FUNCTION "FC_GRP_80_R22" : VOID
TITLE =GROUP =80-R22
{ S7_language := '9(1) Angielski (Stany Zjednoczone)  11.01.2022  09:45:15' }
VERSION : 0.1


VAR_TEMP
  CL : "UDT_CABINET";	//CABINET LOCAL
  CR : "UDT_CABINET";	//CABINET REMOTE
  RelError : BOOL ;	//ERROR RELEASE
  RelErrorCL : BOOL ;	//ERROR RELEASE FROM CABINET LOCAL
  RelErrorCR : BOOL ;	//ERROR RELEASE FROM CABINET REMOTE
  RelControl : BOOL ;	//CONTROL RELEASE
  RelControlCL : BOOL ;	//CONTROL RELEASE FROM CABINET LOCAL
  RelControlCR : BOOL ;	//CONTROL RELEASE FROM CABINET REMOTE
  ErrorConfirm : BOOL ;	//ERROR CONFIRM
  AutoOn : BOOL ;	//AUTOMATIC ON
  AutoOff : BOOL ;	//AUTOMATIC OFF
  AutoOnTemp : BOOL ;
  AutoOffTemp : BOOL ;
  TrDummy : REAL ;	//place holder
  Runtime_DI : DINT ;
  Runtime_R : REAL ;
END_VAR
BEGIN
NETWORK
TITLE =GLOBAL SIGNALS

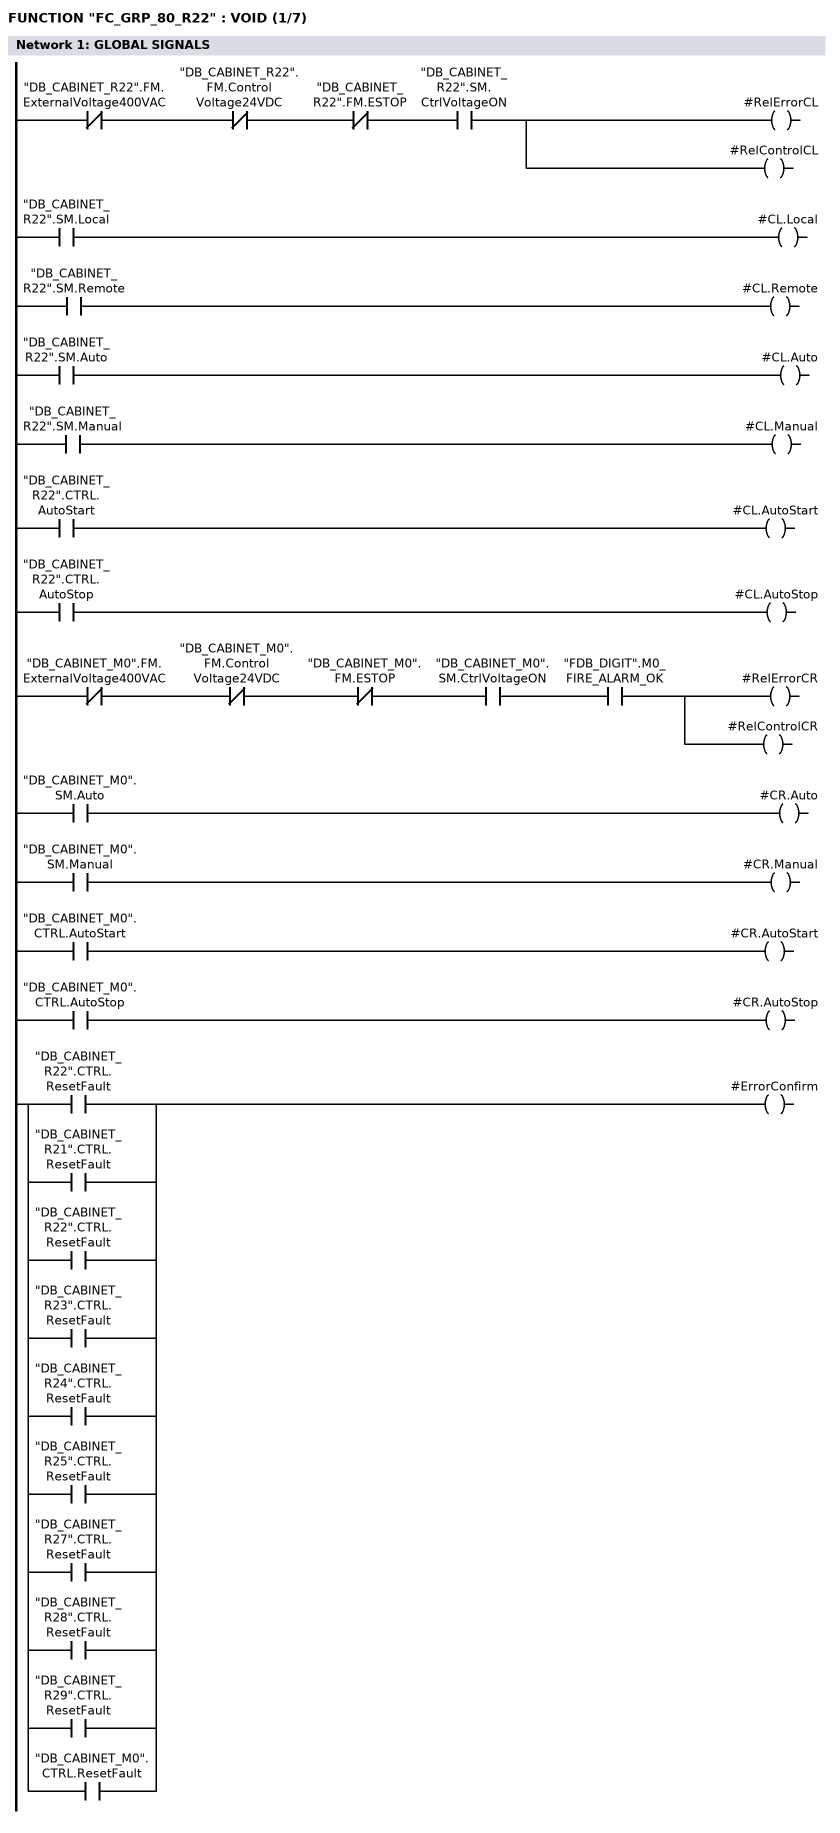
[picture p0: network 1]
// LOCAL
      UN    "DB_CABINET_R22".FM.ExternalVoltage400VAC;
      UN    "DB_CABINET_R22".FM.ControlVoltage24VDC;
      UN    "DB_CABINET_R22".FM.ESTOP;
      U     "DB_CABINET_R22".SM.CtrlVoltageON;
      =     #RelErrorCL;
      =     #RelControlCL;

      U     "DB_CABINET_R22".SM.Local;
      =     #CL.Local;
      U     "DB_CABINET_R22".SM.Remote;
      =     #CL.Remote;
      U     "DB_CABINET_R22".SM.Auto;
      =     #CL.Auto;
      U     "DB_CABINET_R22".SM.Manual;
      =     #CL.Manual;
      U     "DB_CABINET_R22".CTRL.AutoStart;
      =     #CL.AutoStart;
      U     "DB_CABINET_R22".CTRL.AutoStop;
      =     #CL.AutoStop;

// REMOTE
      UN    "DB_CABINET_M0".FM.ExternalVoltage400VAC;
      UN    "DB_CABINET_M0".FM.ControlVoltage24VDC;
      UN    "DB_CABINET_M0".FM.ESTOP;
      U     "DB_CABINET_M0".SM.CtrlVoltageON;
      U     "FDB_DIGIT".M0_FIRE_ALARM_OK;
      =     #RelErrorCR;
      =     #RelControlCR;

      U     "DB_CABINET_M0".SM.Auto;
      =     #CR.Auto;
      U     "DB_CABINET_M0".SM.Manual;
      =     #CR.Manual;
      U     "DB_CABINET_M0".CTRL.AutoStart;
      =     #CR.AutoStart;
      U     "DB_CABINET_M0".CTRL.AutoStop;
      =     #CR.AutoStop;

      U     "DB_CABINET_R22".CTRL.ResetFault;
      O     "DB_CABINET_R21".CTRL.ResetFault;
      O     "DB_CABINET_R22".CTRL.ResetFault;
      O     "DB_CABINET_R23".CTRL.ResetFault;
      O     "DB_CABINET_R24".CTRL.ResetFault;
      O     "DB_CABINET_R25".CTRL.ResetFault;
      O     "DB_CABINET_R27".CTRL.ResetFault;
      O     "DB_CABINET_R28".CTRL.ResetFault;
      O     "DB_CABINET_R29".CTRL.ResetFault;
      O     "DB_CABINET_M0".CTRL.ResetFault;
      =     #ErrorConfirm;
NETWORK
TITLE ==80TAN01-U1 CONTROL/ERROR RELEASE

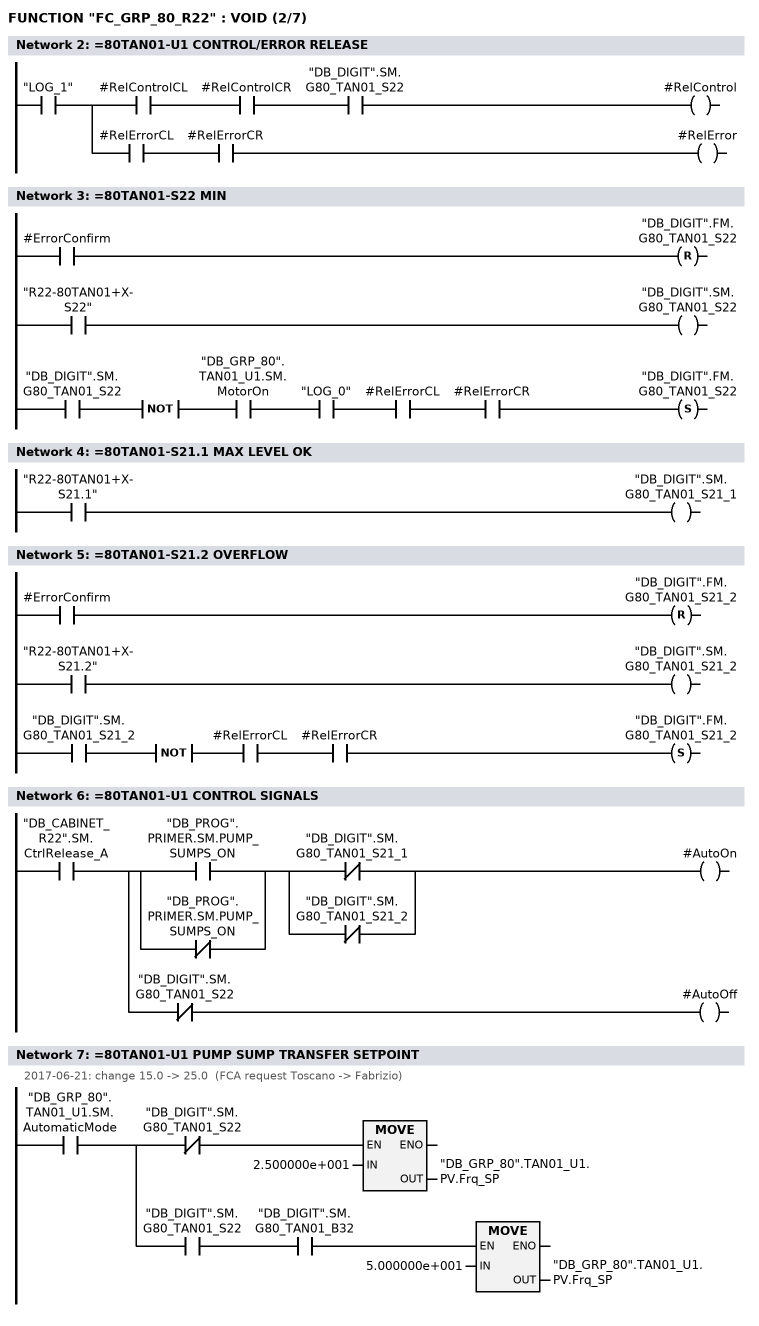
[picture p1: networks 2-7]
      U     "LOG_1";
      =     L     18.0;
      U     L     18.0;
      U     #RelControlCL;
      U     #RelControlCR;
      U     "DB_DIGIT".SM.G80_TAN01_S22;
      =     #RelControl;
      U     L     18.0;
      U     #RelErrorCL;
      U     #RelErrorCR;
      =     #RelError;
NETWORK
TITLE ==80TAN01-S22 MIN

      U     #ErrorConfirm;
      R     "DB_DIGIT".FM.G80_TAN01_S22;
      U     "R22-80TAN01+X-S22";
      =     "DB_DIGIT".SM.G80_TAN01_S22;
      U     "DB_DIGIT".SM.G80_TAN01_S22;
      NOT   ;
      U     "DB_GRP_80".TAN01_U1.SM.MotorOn;
      U     "LOG_0";
      U     #RelErrorCL;
      U     #RelErrorCR;
      S     "DB_DIGIT".FM.G80_TAN01_S22;
      NOP   0;
NETWORK
TITLE ==80TAN01-S21.1 MAX LEVEL OK

      U     "R22-80TAN01+X-S21.1";
      =     "DB_DIGIT".SM.G80_TAN01_S21_1;
NETWORK
TITLE ==80TAN01-S21.2 OVERFLOW

      U     #ErrorConfirm;
      R     "DB_DIGIT".FM.G80_TAN01_S21_2;
      U     "R22-80TAN01+X-S21.2";
      =     "DB_DIGIT".SM.G80_TAN01_S21_2;
      U     "DB_DIGIT".SM.G80_TAN01_S21_2;
      NOT   ;
      U     #RelErrorCL;
      U     #RelErrorCR;
      S     "DB_DIGIT".FM.G80_TAN01_S21_2;
      NOP   0;
NETWORK
TITLE ==80TAN01-U1 CONTROL SIGNALS

      U     "DB_CABINET_R22".SM.CtrlRelease_A;
      =     L     18.0;
      U     L     18.0;
      U(    ;
      O     "DB_PROG".PRIMER.SM.PUMP_SUMPS_ON;
      ON    "DB_PROG".PRIMER.SM.PUMP_SUMPS_ON;
      )     ;
      U(    ;
      ON    "DB_DIGIT".SM.G80_TAN01_S21_1;
      ON    "DB_DIGIT".SM.G80_TAN01_S21_2;
      )     ;
      =     #AutoOn;
      U     L     18.0;
      UN    "DB_DIGIT".SM.G80_TAN01_S22;
      =     #AutoOff;
NETWORK
TITLE ==80TAN01-U1 PUMP SUMP TRANSFER SETPOINT
//2017-06-21: change 15.0 -> 25.0  (FCA request Toscano -> Fabrizio)
      U     "DB_GRP_80".TAN01_U1.SM.AutomaticMode;
      =     L     18.0;
      U     L     18.0;
      UN    "DB_DIGIT".SM.G80_TAN01_S22;
      SPBNB _001;
      L     2.500000e+001;
      T     "DB_GRP_80".TAN01_U1.PV.Frq_SP;
_001: NOP   0;
      U     L     18.0;
      U     "DB_DIGIT".SM.G80_TAN01_S22;
      U     "DB_DIGIT".SM.G80_TAN01_B32;
      SPBNB _002;
      L     5.000000e+001;
      T     "DB_GRP_80".TAN01_U1.PV.Frq_SP;
_002: NOP   0;
NETWORK
TITLE =RESET USING ESTOP ON THE CABINET

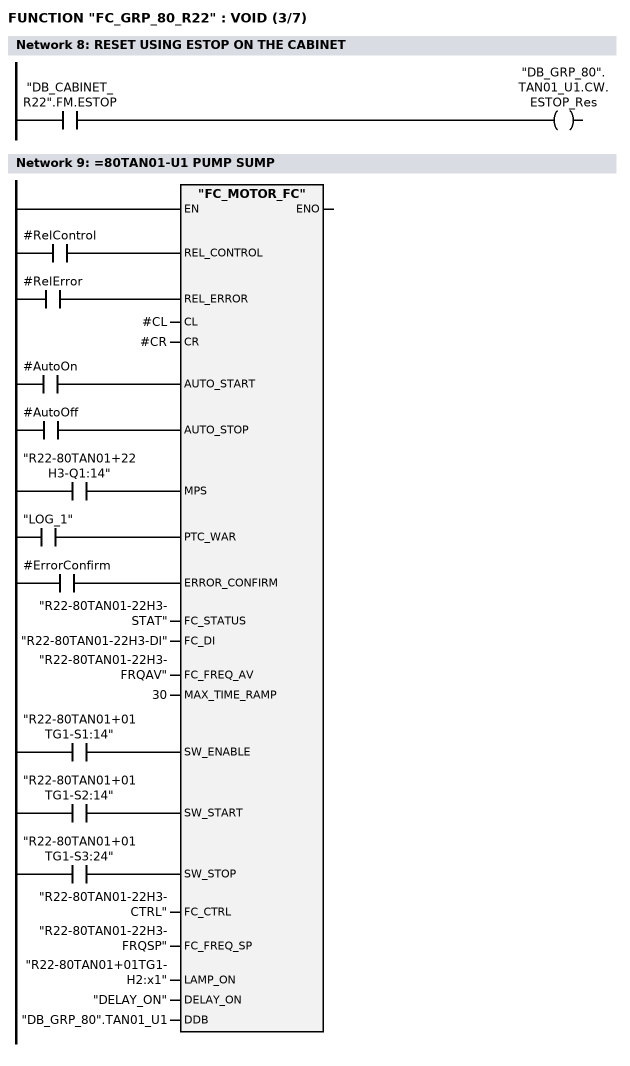
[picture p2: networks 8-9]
      U     "DB_CABINET_R22".FM.ESTOP;
      =     "DB_GRP_80".TAN01_U1.CW.ESTOP_Res;
NETWORK
TITLE ==80TAN01-U1 PUMP SUMP

      U     #RelControl;
      =     L     18.0;
      BLD   103;
      U     #RelError;
      =     L     18.1;
      BLD   103;
      U     #AutoOn;
      =     L     18.2;
      BLD   103;
      U     #AutoOff;
      =     L     18.3;
      BLD   103;
      U     "R22-80TAN01+22H3-Q1:14";
      =     L     18.4;
      BLD   103;
      U     "LOG_1";
      =     L     18.5;
      BLD   103;
      U     #ErrorConfirm;
      =     L     18.6;
      BLD   103;
      U     "R22-80TAN01+01TG1-S1:14";
      =     L     18.7;
      BLD   103;
      U     "R22-80TAN01+01TG1-S2:14";
      =     L     19.0;
      BLD   103;
      U     "R22-80TAN01+01TG1-S3:24";
      =     L     19.1;
      BLD   103;
      CALL "FC_MOTOR_FC" (
           REL_CONTROL              := L     18.0,
           REL_ERROR                := L     18.1,
           CL                       := #CL,
           CR                       := #CR,
           AUTO_START               := L     18.2,
           AUTO_STOP                := L     18.3,
           MPS                      := L     18.4,
           PTC_WAR                  := L     18.5,
           ERROR_CONFIRM            := L     18.6,
           FC_STATUS                := "R22-80TAN01-22H3-STAT",
           FC_DI                    := "R22-80TAN01-22H3-DI",
           FC_FREQ_AV               := "R22-80TAN01-22H3-FRQAV",
           MAX_TIME_RAMP            := 30,
           SW_ENABLE                := L     18.7,
           SW_START                 := L     19.0,
           SW_STOP                  := L     19.1,
           FC_CTRL                  := "R22-80TAN01-22H3-CTRL",
           FC_FREQ_SP               := "R22-80TAN01-22H3-FRQSP",
           LAMP_ON                  := "R22-80TAN01+01TG1-H2:x1",
           DELAY_ON                 := "DELAY_ON",
           DDB                      := "DB_GRP_80".TAN01_U1);
      NOP   0;
NETWORK
TITLE ==80TAN01-S32F PRESSURE MONITORING

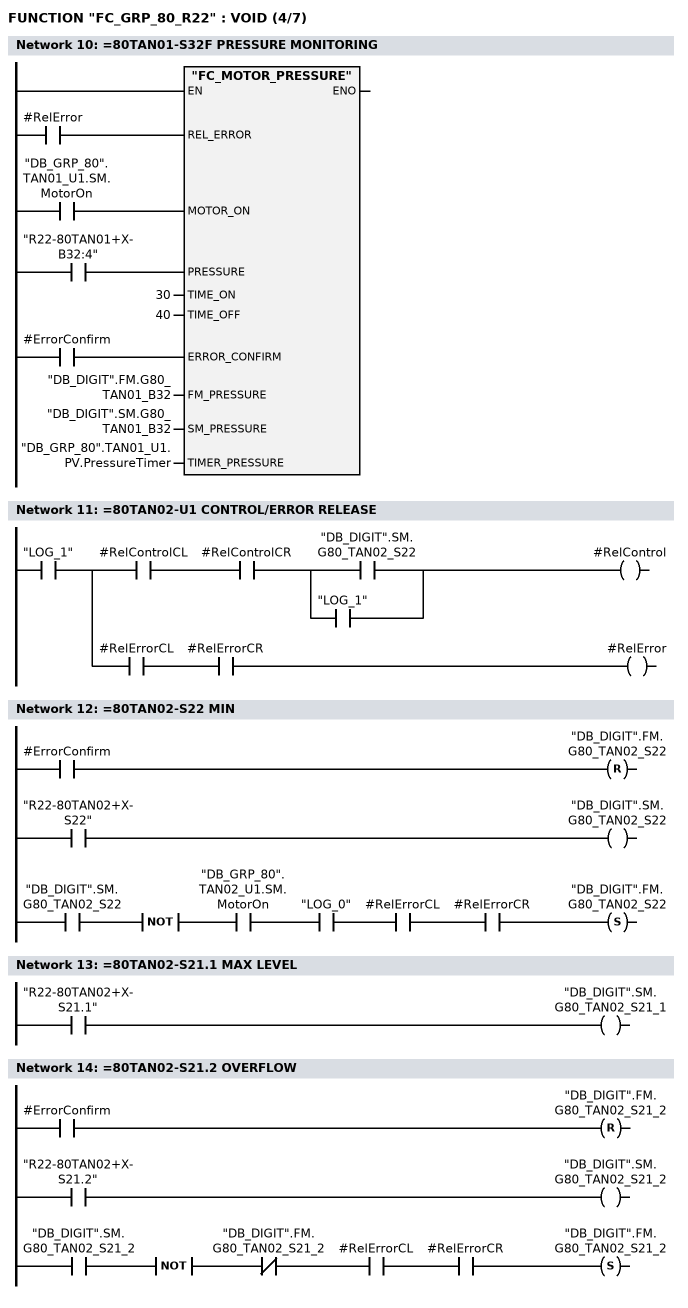
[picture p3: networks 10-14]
      U     #RelError;
      =     L     18.0;
      BLD   103;
      U     "DB_GRP_80".TAN01_U1.SM.MotorOn;
      =     L     18.1;
      BLD   103;
      U     "R22-80TAN01+X-B32:4";
      =     L     18.2;
      BLD   103;
      U     #ErrorConfirm;
      =     L     18.3;
      BLD   103;
      CALL "FC_MOTOR_PRESSURE" (
           REL_ERROR                := L     18.0,
           MOTOR_ON                 := L     18.1,
           PRESSURE                 := L     18.2,
           TIME_ON                  := 30,
           TIME_OFF                 := 40,
           ERROR_CONFIRM            := L     18.3,
           FM_PRESSURE              := "DB_DIGIT".FM.G80_TAN01_B32,
           SM_PRESSURE              := "DB_DIGIT".SM.G80_TAN01_B32,
           TIMER_PRESSURE           := "DB_GRP_80".TAN01_U1.PV.PressureTimer);
      NOP   0;
NETWORK
TITLE ==80TAN02-U1 CONTROL/ERROR RELEASE

      U     "LOG_1";
      =     L     18.0;
      U     L     18.0;
      U     #RelControlCL;
      U     #RelControlCR;
      U(    ;
      O     "DB_DIGIT".SM.G80_TAN02_S22;
      O     "LOG_1";
      )     ;
      =     #RelControl;
      U     L     18.0;
      U     #RelErrorCL;
      U     #RelErrorCR;
      =     #RelError;
NETWORK
TITLE ==80TAN02-S22 MIN

      U     #ErrorConfirm;
      R     "DB_DIGIT".FM.G80_TAN02_S22;
      U     "R22-80TAN02+X-S22";
      =     "DB_DIGIT".SM.G80_TAN02_S22;
      U     "DB_DIGIT".SM.G80_TAN02_S22;
      NOT   ;
      U     "DB_GRP_80".TAN02_U1.SM.MotorOn;
      U     "LOG_0";
      U     #RelErrorCL;
      U     #RelErrorCR;
      S     "DB_DIGIT".FM.G80_TAN02_S22;
      NOP   0;
NETWORK
TITLE ==80TAN02-S21.1 MAX LEVEL

      U     "R22-80TAN02+X-S21.1";
      =     "DB_DIGIT".SM.G80_TAN02_S21_1;
NETWORK
TITLE ==80TAN02-S21.2 OVERFLOW

      U     #ErrorConfirm;
      R     "DB_DIGIT".FM.G80_TAN02_S21_2;
      U     "R22-80TAN02+X-S21.2";
      =     "DB_DIGIT".SM.G80_TAN02_S21_2;
      U     "DB_DIGIT".SM.G80_TAN02_S21_2;
      NOT   ;
      UN    "DB_DIGIT".FM.G80_TAN02_S21_2;
      U     #RelErrorCL;
      U     #RelErrorCR;
      S     "DB_DIGIT".FM.G80_TAN02_S21_2;
      NOP   0;
NETWORK
TITLE ==80TAN02-U1 CONTROL SIGNALS

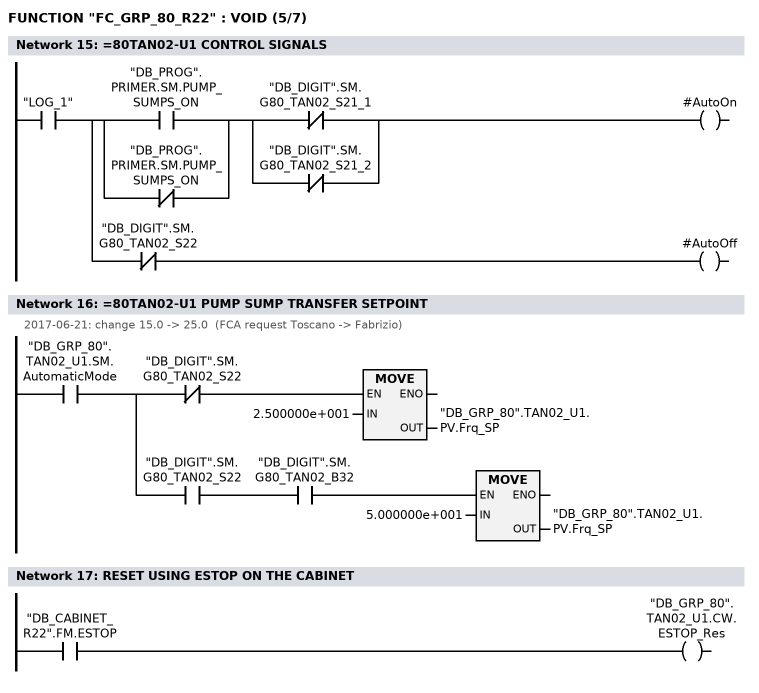
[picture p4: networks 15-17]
      U     "LOG_1";
      =     L     18.0;
      U     L     18.0;
      U(    ;
      O     "DB_PROG".PRIMER.SM.PUMP_SUMPS_ON;
      ON    "DB_PROG".PRIMER.SM.PUMP_SUMPS_ON;
      )     ;
      U(    ;
      ON    "DB_DIGIT".SM.G80_TAN02_S21_1;
      ON    "DB_DIGIT".SM.G80_TAN02_S21_2;
      )     ;
      =     #AutoOn;
      U     L     18.0;
      UN    "DB_DIGIT".SM.G80_TAN02_S22;
      =     #AutoOff;
NETWORK
TITLE ==80TAN02-U1 PUMP SUMP TRANSFER SETPOINT
//2017-06-21: change 15.0 -> 25.0  (FCA request Toscano -> Fabrizio)
      U     "DB_GRP_80".TAN02_U1.SM.AutomaticMode;
      =     L     18.0;
      U     L     18.0;
      UN    "DB_DIGIT".SM.G80_TAN02_S22;
      SPBNB _003;
      L     2.500000e+001;
      T     "DB_GRP_80".TAN02_U1.PV.Frq_SP;
_003: NOP   0;
      U     L     18.0;
      U     "DB_DIGIT".SM.G80_TAN02_S22;
      U     "DB_DIGIT".SM.G80_TAN02_B32;
      SPBNB _004;
      L     5.000000e+001;
      T     "DB_GRP_80".TAN02_U1.PV.Frq_SP;
_004: NOP   0;
NETWORK
TITLE =RESET USING ESTOP ON THE CABINET

      U     "DB_CABINET_R22".FM.ESTOP;
      =     "DB_GRP_80".TAN02_U1.CW.ESTOP_Res;
NETWORK
TITLE ==80TAN02-U1 PUMP SUMP

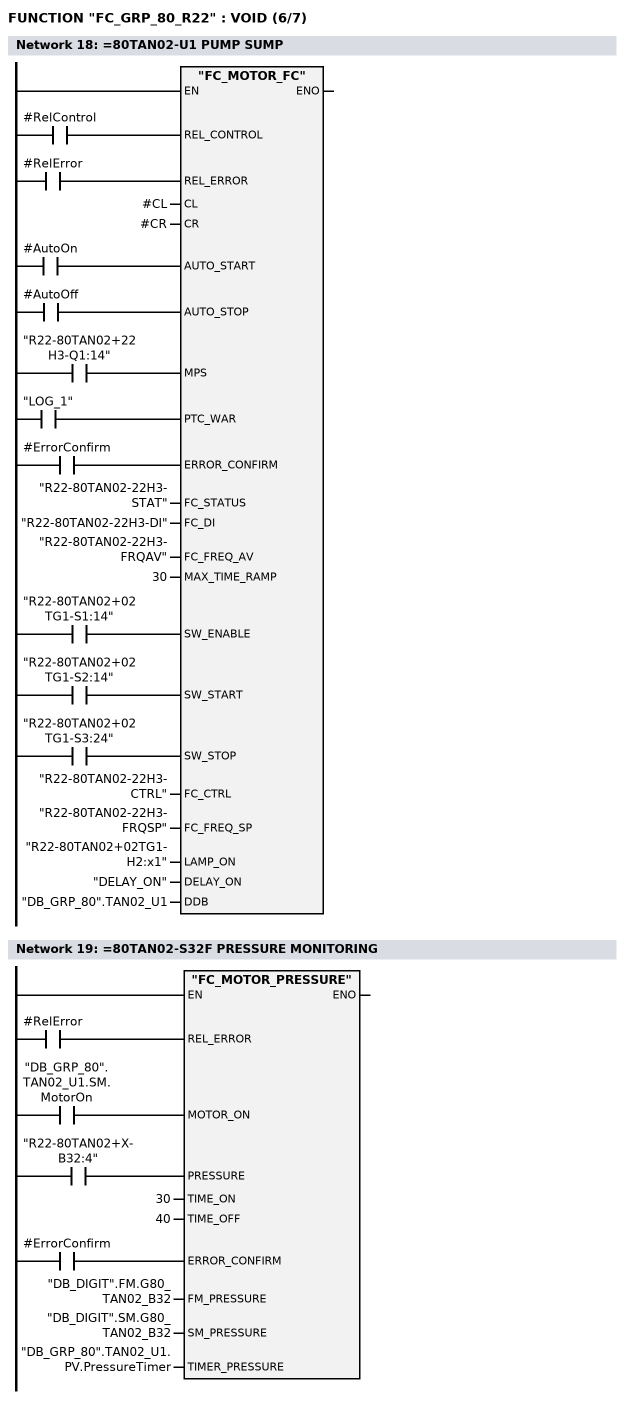
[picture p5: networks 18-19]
      U     #RelControl;
      =     L     18.0;
      BLD   103;
      U     #RelError;
      =     L     18.1;
      BLD   103;
      U     #AutoOn;
      =     L     18.2;
      BLD   103;
      U     #AutoOff;
      =     L     18.3;
      BLD   103;
      U     "R22-80TAN02+22H3-Q1:14";
      =     L     18.4;
      BLD   103;
      U     "LOG_1";
      =     L     18.5;
      BLD   103;
      U     #ErrorConfirm;
      =     L     18.6;
      BLD   103;
      U     "R22-80TAN02+02TG1-S1:14";
      =     L     18.7;
      BLD   103;
      U     "R22-80TAN02+02TG1-S2:14";
      =     L     19.0;
      BLD   103;
      U     "R22-80TAN02+02TG1-S3:24";
      =     L     19.1;
      BLD   103;
      CALL "FC_MOTOR_FC" (
           REL_CONTROL              := L     18.0,
           REL_ERROR                := L     18.1,
           CL                       := #CL,
           CR                       := #CR,
           AUTO_START               := L     18.2,
           AUTO_STOP                := L     18.3,
           MPS                      := L     18.4,
           PTC_WAR                  := L     18.5,
           ERROR_CONFIRM            := L     18.6,
           FC_STATUS                := "R22-80TAN02-22H3-STAT",
           FC_DI                    := "R22-80TAN02-22H3-DI",
           FC_FREQ_AV               := "R22-80TAN02-22H3-FRQAV",
           MAX_TIME_RAMP            := 30,
           SW_ENABLE                := L     18.7,
           SW_START                 := L     19.0,
           SW_STOP                  := L     19.1,
           FC_CTRL                  := "R22-80TAN02-22H3-CTRL",
           FC_FREQ_SP               := "R22-80TAN02-22H3-FRQSP",
           LAMP_ON                  := "R22-80TAN02+02TG1-H2:x1",
           DELAY_ON                 := "DELAY_ON",
           DDB                      := "DB_GRP_80".TAN02_U1);
      NOP   0;
NETWORK
TITLE ==80TAN02-S32F PRESSURE MONITORING

      U     #RelError;
      =     L     18.0;
      BLD   103;
      U     "DB_GRP_80".TAN02_U1.SM.MotorOn;
      =     L     18.1;
      BLD   103;
      U     "R22-80TAN02+X-B32:4";
      =     L     18.2;
      BLD   103;
      U     #ErrorConfirm;
      =     L     18.3;
      BLD   103;
      CALL "FC_MOTOR_PRESSURE" (
           REL_ERROR                := L     18.0,
           MOTOR_ON                 := L     18.1,
           PRESSURE                 := L     18.2,
           TIME_ON                  := 30,
           TIME_OFF                 := 40,
           ERROR_CONFIRM            := L     18.3,
           FM_PRESSURE              := "DB_DIGIT".FM.G80_TAN02_B32,
           SM_PRESSURE              := "DB_DIGIT".SM.G80_TAN02_B32,
           TIMER_PRESSURE           := "DB_GRP_80".TAN02_U1.PV.PressureTimer);
      NOP   0;
NETWORK
TITLE ==80FLA60-M1 CONTROL/ERROR RELEASE

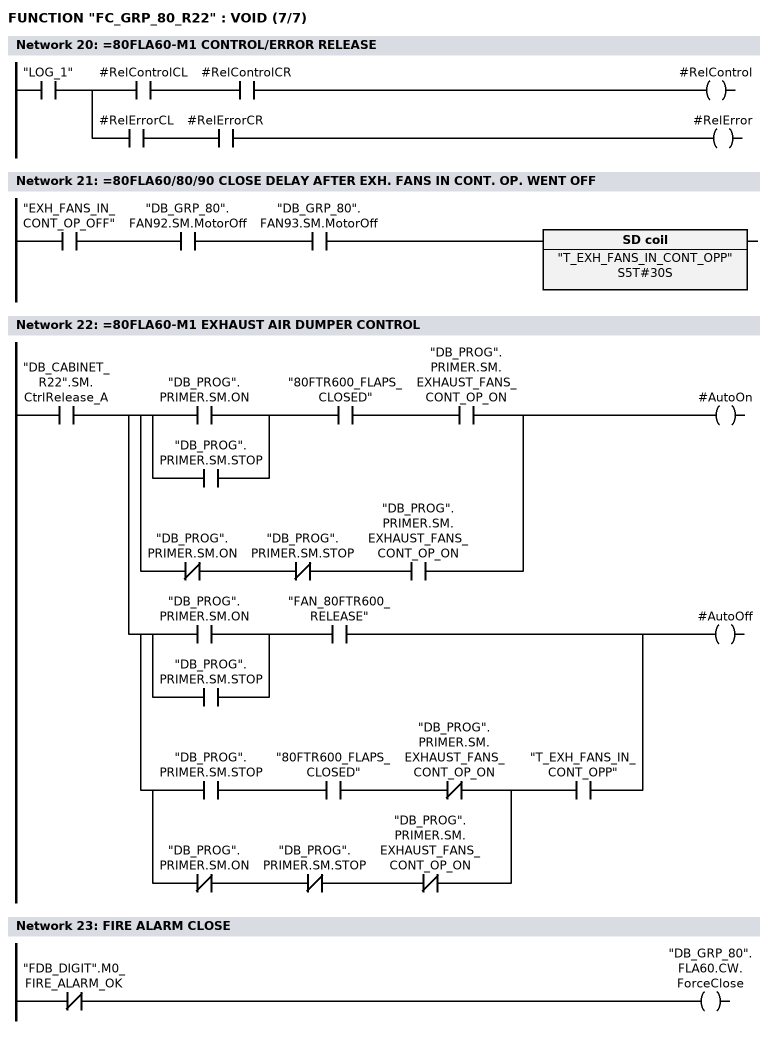
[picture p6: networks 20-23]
      U     "LOG_1";
      =     L     18.0;
      U     L     18.0;
      U     #RelControlCL;
      U     #RelControlCR;
      =     #RelControl;
      U     L     18.0;
      U     #RelErrorCL;
      U     #RelErrorCR;
      =     #RelError;
NETWORK
TITLE ==80FLA60/80/90 CLOSE DELAY AFTER EXH. FANS IN CONT. OP. WENT OFF

      U     "EXH_FANS_IN_CONT_OP_OFF";
      U     "DB_GRP_80".FAN92.SM.MotorOff;
      U     "DB_GRP_80".FAN93.SM.MotorOff;
      L     S5T#30S;
      SE    "T_EXH_FANS_IN_CONT_OPP";
      NOP   0;
      NOP   0;
      NOP   0;
      NOP   0;
NETWORK
TITLE ==80FLA60-M1 EXHAUST AIR DUMPER CONTROL

      U     "DB_CABINET_R22".SM.CtrlRelease_A;
      =     L     18.0;
      U     L     18.0;
      U(    ;
      U(    ;
      O     "DB_PROG".PRIMER.SM.ON;
      O     "DB_PROG".PRIMER.SM.STOP;
      )     ;
      U     "80FTR600_FLAPS_CLOSED";
      U     "DB_PROG".PRIMER.SM.EXHAUST_FANS_CONT_OP_ON;
      O     ;
      UN    "DB_PROG".PRIMER.SM.ON;
      UN    "DB_PROG".PRIMER.SM.STOP;
      U     "DB_PROG".PRIMER.SM.EXHAUST_FANS_CONT_OP_ON;
      )     ;
      =     #AutoOn;
      U     L     18.0;
      U(    ;
      U(    ;
      O     "DB_PROG".PRIMER.SM.ON;
      O     "DB_PROG".PRIMER.SM.STOP;
      )     ;
      U     "FAN_80FTR600_RELEASE";
      O     ;
      U(    ;
      U     "DB_PROG".PRIMER.SM.STOP;
      U     "80FTR600_FLAPS_CLOSED";
      UN    "DB_PROG".PRIMER.SM.EXHAUST_FANS_CONT_OP_ON;
      O     ;
      UN    "DB_PROG".PRIMER.SM.ON;
      UN    "DB_PROG".PRIMER.SM.STOP;
      UN    "DB_PROG".PRIMER.SM.EXHAUST_FANS_CONT_OP_ON;
      )     ;
      U     "T_EXH_FANS_IN_CONT_OPP";
      )     ;
      =     #AutoOff;
NETWORK
TITLE =FIRE ALARM CLOSE

      UN    "FDB_DIGIT".M0_FIRE_ALARM_OK;
      =     "DB_GRP_80".FLA60.CW.ForceClose;
NETWORK
TITLE ==80FLA60-M1 EXHAUST AIR DUMPER

      U     #RelControl;
      =     L     18.0;
      BLD   103;
      U     #RelError;
      =     L     18.1;
      BLD   103;
      U     #AutoOn;
      =     L     18.2;
      BLD   103;
      U     #AutoOff;
      =     L     18.3;
      BLD   103;
      U     "LOG_1";
      =     L     18.4;
      BLD   103;
      U(    ;
      U     "R22-80FLA60+X-S1C.1:4";
      L     S5T#15S;
      SE    "T_80FLA60_LS_O";
      UN    "R22-80FLA60+X-S1C.1:4";
      R     "T_80FLA60_LS_O";
      NOP   0;
      NOP   0;
      U     "T_80FLA60_LS_O";
      )     ;
      =     L     18.5;
      BLD   103;
      U     "80FLA60_Close";
      =     L     18.6;
      BLD   103;
      U     #ErrorConfirm;
      =     L     18.7;
      BLD   103;
      CALL "FC_FLAP" (
           REL_CONTROL              := L     18.0,
           REL_ERROR                := L     18.1,
           CL                       := #CL,
           CR                       := #CR,
           AUTO_OPEN                := L     18.2,
           AUTO_CLOSE               := L     18.3,
           FUSE                     := L     18.4,
           LS_OPEN                  := L     18.5,
           LS_CLOSE                 := L     18.6,
           ERROR_CONFIRM            := L     18.7,
           MAX_RUNTIME              := 180,
           OPEN                     := "R22-80FLA60+X-M1:2",
           CLOSE                    := "R22-80FLA60+X-M1:3",
           DDB                      := "DB_GRP_80".FLA60);
      NOP   0;
NETWORK
TITLE =80FLA60-M1 TIME BASED CLOSE LIMIT SWITCH

      U(    ;
      U     "R22-80FLA60+X-M1:3";
      L     S5T#2M20S;
      SE    "T_80FLA60_LS_C";
      U     "R22-80FLA60+X-M1:2";
      R     "T_80FLA60_LS_C";
      NOP   0;
      NOP   0;
      U     "T_80FLA60_LS_C";
      )     ;
      S     "80FLA60_Close";
      U     "R22-80FLA60+X-M1:2";
      R     "80FLA60_Close";
      NOP   0;
NETWORK
TITLE ==80FLA80-M1 CONTROL/ERROR RELEASE

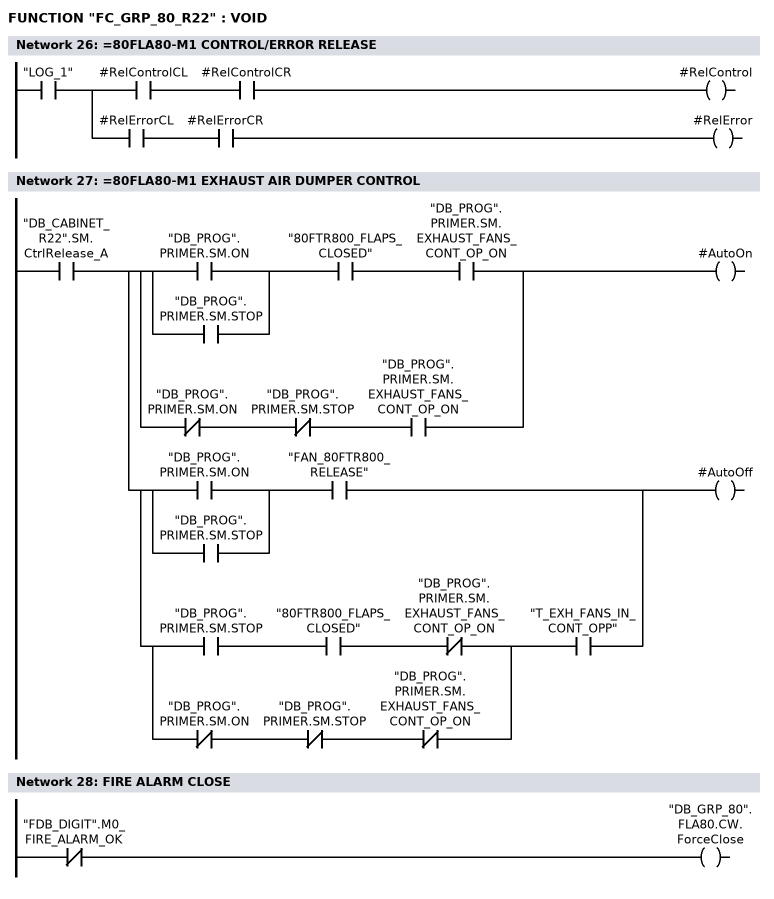
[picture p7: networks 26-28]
      U     "LOG_1";
      =     L     18.0;
      U     L     18.0;
      U     #RelControlCL;
      U     #RelControlCR;
      =     #RelControl;
      U     L     18.0;
      U     #RelErrorCL;
      U     #RelErrorCR;
      =     #RelError;
NETWORK
TITLE ==80FLA80-M1 EXHAUST AIR DUMPER CONTROL

      U     "DB_CABINET_R22".SM.CtrlRelease_A;
      =     L     18.0;
      U     L     18.0;
      U(    ;
      U(    ;
      O     "DB_PROG".PRIMER.SM.ON;
      O     "DB_PROG".PRIMER.SM.STOP;
      )     ;
      U     "80FTR800_FLAPS_CLOSED";
      U     "DB_PROG".PRIMER.SM.EXHAUST_FANS_CONT_OP_ON;
      O     ;
      UN    "DB_PROG".PRIMER.SM.ON;
      UN    "DB_PROG".PRIMER.SM.STOP;
      U     "DB_PROG".PRIMER.SM.EXHAUST_FANS_CONT_OP_ON;
      )     ;
      =     #AutoOn;
      U     L     18.0;
      U(    ;
      U(    ;
      O     "DB_PROG".PRIMER.SM.ON;
      O     "DB_PROG".PRIMER.SM.STOP;
      )     ;
      U     "FAN_80FTR800_RELEASE";
      O     ;
      U(    ;
      U     "DB_PROG".PRIMER.SM.STOP;
      U     "80FTR800_FLAPS_CLOSED";
      UN    "DB_PROG".PRIMER.SM.EXHAUST_FANS_CONT_OP_ON;
      O     ;
      UN    "DB_PROG".PRIMER.SM.ON;
      UN    "DB_PROG".PRIMER.SM.STOP;
      UN    "DB_PROG".PRIMER.SM.EXHAUST_FANS_CONT_OP_ON;
      )     ;
      U     "T_EXH_FANS_IN_CONT_OPP";
      )     ;
      =     #AutoOff;
NETWORK
TITLE =FIRE ALARM CLOSE

      UN    "FDB_DIGIT".M0_FIRE_ALARM_OK;
      =     "DB_GRP_80".FLA80.CW.ForceClose;
NETWORK
TITLE ==80FLA80-M1 EXHAUST AIR DUMPER

      U     #RelControl;
      =     L     18.0;
      BLD   103;
      U     #RelError;
      =     L     18.1;
      BLD   103;
      U     #AutoOn;
      =     L     18.2;
      BLD   103;
      U     #AutoOff;
      =     L     18.3;
      BLD   103;
      U     "LOG_1";
      =     L     18.4;
      BLD   103;
      U(    ;
      U     "R22-80FLA80+X-S1C.1:4";
      L     S5T#15S;
      SE    "T_80FLA80_LS_O";
      NOP   0;
      NOP   0;
      NOP   0;
      U     "T_80FLA80_LS_O";
      )     ;
      =     L     18.5;
      BLD   103;
      U     "80FLA80_Close";
      =     L     18.6;
      BLD   103;
      U     #ErrorConfirm;
      =     L     18.7;
      BLD   103;
      CALL "FC_FLAP" (
           REL_CONTROL              := L     18.0,
           REL_ERROR                := L     18.1,
           CL                       := #CL,
           CR                       := #CR,
           AUTO_OPEN                := L     18.2,
           AUTO_CLOSE               := L     18.3,
           FUSE                     := L     18.4,
           LS_OPEN                  := L     18.5,
           LS_CLOSE                 := L     18.6,
           ERROR_CONFIRM            := L     18.7,
           MAX_RUNTIME              := 190,
           OPEN                     := "R22-80FLA80+X-M1:2",
           CLOSE                    := "R22-80FLA80+X-M1:3",
           DDB                      := "DB_GRP_80".FLA80);
      NOP   0;
NETWORK
TITLE =DELAY OF 80FLA80-M1 CLOSE LIMIT SWITCH

      U(    ;
      U     "R22-80FLA80+X-M1:3";
      L     S5T#2M15S;
      SE    "T_80FLA80_LS_C";
      U     "R22-80FLA80+X-M1:2";
      R     "T_80FLA80_LS_C";
      NOP   0;
      NOP   0;
      U     "T_80FLA80_LS_C";
      )     ;
      S     "80FLA80_Close";
      U     "R22-80FLA80+X-M1:2";
      R     "80FLA80_Close";
      NOP   0;
NETWORK
TITLE ==80FLA90-M1 CONTROL/ERROR RELEASE

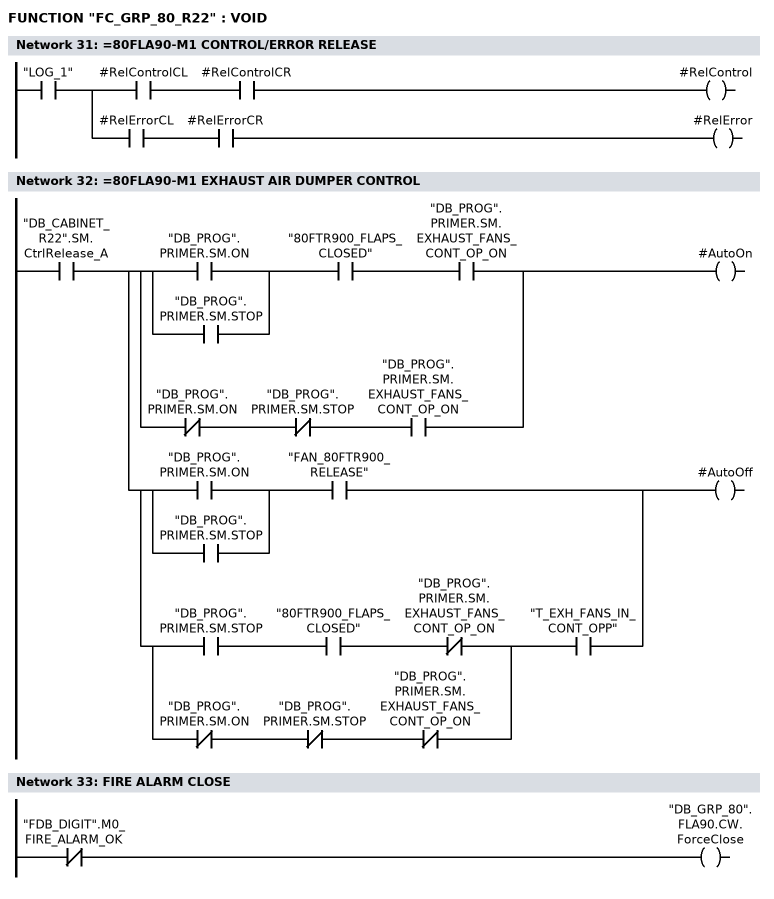
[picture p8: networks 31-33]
      U     "LOG_1";
      =     L     18.0;
      U     L     18.0;
      U     #RelControlCL;
      U     #RelControlCR;
      =     #RelControl;
      U     L     18.0;
      U     #RelErrorCL;
      U     #RelErrorCR;
      =     #RelError;
NETWORK
TITLE ==80FLA90-M1 EXHAUST AIR DUMPER CONTROL

      U     "DB_CABINET_R22".SM.CtrlRelease_A;
      =     L     18.0;
      U     L     18.0;
      U(    ;
      U(    ;
      O     "DB_PROG".PRIMER.SM.ON;
      O     "DB_PROG".PRIMER.SM.STOP;
      )     ;
      U     "80FTR900_FLAPS_CLOSED";
      U     "DB_PROG".PRIMER.SM.EXHAUST_FANS_CONT_OP_ON;
      O     ;
      UN    "DB_PROG".PRIMER.SM.ON;
      UN    "DB_PROG".PRIMER.SM.STOP;
      U     "DB_PROG".PRIMER.SM.EXHAUST_FANS_CONT_OP_ON;
      )     ;
      =     #AutoOn;
      U     L     18.0;
      U(    ;
      U(    ;
      O     "DB_PROG".PRIMER.SM.ON;
      O     "DB_PROG".PRIMER.SM.STOP;
      )     ;
      U     "FAN_80FTR900_RELEASE";
      O     ;
      U(    ;
      U     "DB_PROG".PRIMER.SM.STOP;
      U     "80FTR900_FLAPS_CLOSED";
      UN    "DB_PROG".PRIMER.SM.EXHAUST_FANS_CONT_OP_ON;
      O     ;
      UN    "DB_PROG".PRIMER.SM.ON;
      UN    "DB_PROG".PRIMER.SM.STOP;
      UN    "DB_PROG".PRIMER.SM.EXHAUST_FANS_CONT_OP_ON;
      )     ;
      U     "T_EXH_FANS_IN_CONT_OPP";
      )     ;
      =     #AutoOff;
NETWORK
TITLE =FIRE ALARM CLOSE

      UN    "FDB_DIGIT".M0_FIRE_ALARM_OK;
      =     "DB_GRP_80".FLA90.CW.ForceClose;
NETWORK
TITLE ==80FLA90-M1 EXHAUST AIR DUMPER

      U     #RelControl;
      =     L     18.0;
      BLD   103;
      U     #RelError;
      =     L     18.1;
      BLD   103;
      U     #AutoOn;
      =     L     18.2;
      BLD   103;
      U     #AutoOff;
      =     L     18.3;
      BLD   103;
      U     "LOG_1";
      =     L     18.4;
      BLD   103;
      U(    ;
      U     "R22-80FLA90+X-S1C.1:4";
      L     S5T#15S;
      SE    "T_80FLA90_LS_O";
      NOP   0;
      NOP   0;
      NOP   0;
      U     "T_80FLA90_LS_O";
      )     ;
      =     L     18.5;
      BLD   103;
      U     "80FLA90_Close";
      =     L     18.6;
      BLD   103;
      U     #ErrorConfirm;
      =     L     18.7;
      BLD   103;
      CALL "FC_FLAP" (
           REL_CONTROL              := L     18.0,
           REL_ERROR                := L     18.1,
           CL                       := #CL,
           CR                       := #CR,
           AUTO_OPEN                := L     18.2,
           AUTO_CLOSE               := L     18.3,
           FUSE                     := L     18.4,
           LS_OPEN                  := L     18.5,
           LS_CLOSE                 := L     18.6,
           ERROR_CONFIRM            := L     18.7,
           MAX_RUNTIME              := 65,
           OPEN                     := "80FLA90_Opening",
           CLOSE                    := "R22-80FLA90+X-M1:3",
           DDB                      := "DB_GRP_80".FLA90);
      NOP   0;
NETWORK
TITLE =KEEP CLOSING 80FLA90 EVEN IS LS IS REACHED

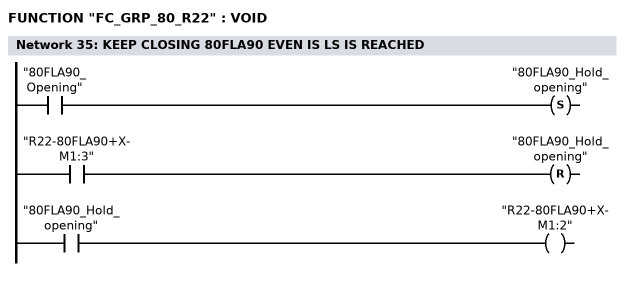
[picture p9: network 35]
      U     "80FLA90_Opening";
      S     "80FLA90_Hold_opening";
      U     "R22-80FLA90+X-M1:3";
      R     "80FLA90_Hold_opening";
      U     "80FLA90_Hold_opening";
      =     "R22-80FLA90+X-M1:2";
NETWORK
TITLE =DELAY OF 80FLA90-M1 CLOSE LIMIT SWITCH

      U(    ;
      U     "R22-80FLA90+X-M1:3";
      L     S5T#16S;
      SE    "T_80FLA90_LS_C";
      U     "R22-80FLA90+X-M1:2";
      R     "T_80FLA90_LS_C";
      NOP   0;
      NOP   0;
      U     "T_80FLA90_LS_C";
      )     ;
      S     "80FLA90_Close";
      U     "R22-80FLA90+X-M1:2";
      R     "80FLA90_Close";
      NOP   0;
NETWORK
TITLE ==80FLA97-M1 CONTROL/ERROR RELEASE (MASTER)

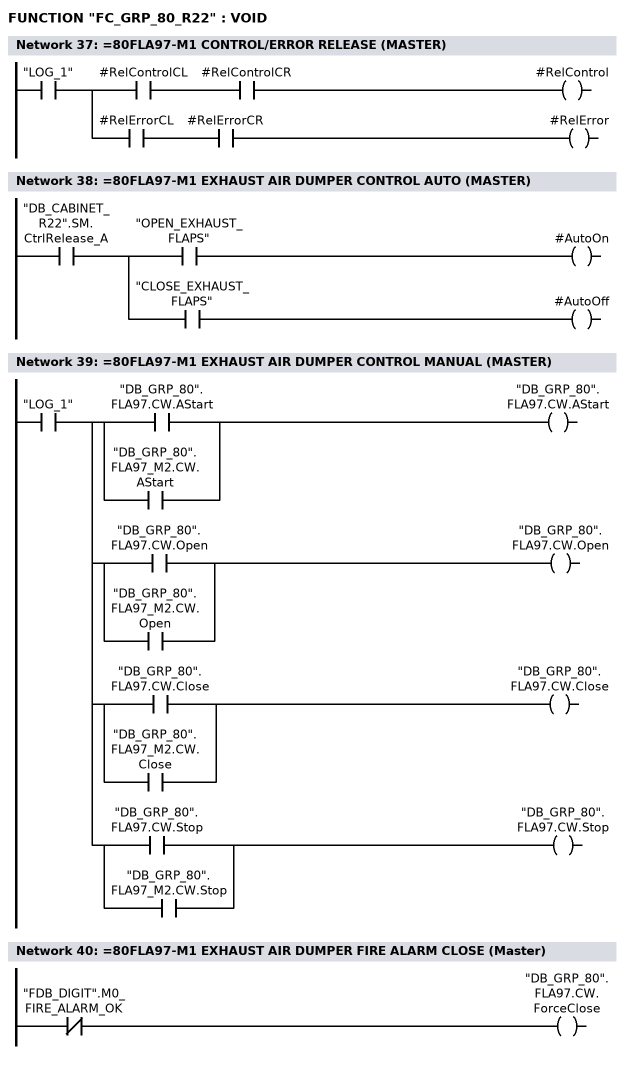
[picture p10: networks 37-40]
      U     "LOG_1";
      =     L     18.0;
      U     L     18.0;
      U     #RelControlCL;
      U     #RelControlCR;
      =     #RelControl;
      U     L     18.0;
      U     #RelErrorCL;
      U     #RelErrorCR;
      =     #RelError;
NETWORK
TITLE ==80FLA97-M1 EXHAUST AIR DUMPER CONTROL AUTO (MASTER)

      U     "DB_CABINET_R22".SM.CtrlRelease_A;
      =     L     18.0;
      U     L     18.0;
      U     "OPEN_EXHAUST_FLAPS";
      =     #AutoOn;
      U     L     18.0;
      U     "CLOSE_EXHAUST_FLAPS";
      =     #AutoOff;
NETWORK
TITLE ==80FLA97-M1 EXHAUST AIR DUMPER CONTROL MANUAL (MASTER)

      U     "LOG_1";
      =     L     18.0;
      U     L     18.0;
      U(    ;
      O     "DB_GRP_80".FLA97.CW.AStart;
      O     "DB_GRP_80".FLA97_M2.CW.AStart;
      )     ;
      =     "DB_GRP_80".FLA97.CW.AStart;
      U     L     18.0;
      U(    ;
      O     "DB_GRP_80".FLA97.CW.Open;
      O     "DB_GRP_80".FLA97_M2.CW.Open;
      )     ;
      =     "DB_GRP_80".FLA97.CW.Open;
      U     L     18.0;
      U(    ;
      O     "DB_GRP_80".FLA97.CW.Close;
      O     "DB_GRP_80".FLA97_M2.CW.Close;
      )     ;
      =     "DB_GRP_80".FLA97.CW.Close;
      U     L     18.0;
      U(    ;
      O     "DB_GRP_80".FLA97.CW.Stop;
      O     "DB_GRP_80".FLA97_M2.CW.Stop;
      )     ;
      =     "DB_GRP_80".FLA97.CW.Stop;
NETWORK
TITLE ==80FLA97-M1 EXHAUST AIR DUMPER FIRE ALARM CLOSE (Master)

      UN    "FDB_DIGIT".M0_FIRE_ALARM_OK;
      =     "DB_GRP_80".FLA97.CW.ForceClose;
NETWORK
TITLE ==80FLA97-M1 EXHAUST AIR DUMPER (Master)

      U     #RelControl;
      =     L     18.0;
      BLD   103;
      U     #RelError;
      =     L     18.1;
      BLD   103;
      U(    ;
      O     "apertura flap";
      O     #AutoOn;
      )     ;
      =     L     18.2;
      BLD   103;
      U(    ;
      O     M     52.1;
      O     #AutoOff;
      )     ;
      UN    "apertura flap";
      =     L     18.3;
      BLD   103;
      U     "LOG_1";
      =     L     18.4;
      BLD   103;
      U(    ;
      U     "R22-80FLA97+X-S1C.1:4";
      U(    ;
      L     "DB_GRP_80".FLA97.PV.Position;
      L     9.500000e+001;
      >R    ;
      )     ;
      L     S5T#10S;
      SE    "T_80FLA97_LS_O";
      NOP   0;
      NOP   0;
      NOP   0;
      U     "T_80FLA97_LS_O";
      )     ;
      =     L     18.5;
      BLD   103;
      U(    ;
      UN    "R22-80FLA97+X-S1C.1:4";
      U(    ;
      L     "DB_GRP_80".FLA97.PV.Position;
      L     2.000000e+000;
      <R    ;
      )     ;
      L     S5T#10S;
      SE    "T_80FLA97_LS_C";
      NOP   0;
      NOP   0;
      NOP   0;
      U     "T_80FLA97_LS_C";
      )     ;
      =     L     18.6;
      BLD   103;
      U     #ErrorConfirm;
      =     L     18.7;
      BLD   103;
      CALL "FC_FLAP" (
           REL_CONTROL              := L     18.0,
           REL_ERROR                := L     18.1,
           CL                       := #CL,
           CR                       := #CR,
           AUTO_OPEN                := L     18.2,
           AUTO_CLOSE               := L     18.3,
           FUSE                     := L     18.4,
           LS_OPEN                  := L     18.5,
           LS_CLOSE                 := L     18.6,
           ERROR_CONFIRM            := L     18.7,
           MAX_RUNTIME              := 200,
           OPEN                     := "R22-80FLA97+X-M1:2",
           CLOSE                    := "R22-80FLA97+X-M1:3",
           DDB                      := "DB_GRP_80".FLA97);
      NOP   0;
NETWORK
TITLE ==80FLA97-M1 EXHAUST AIR DUMPER POSITION (Master)

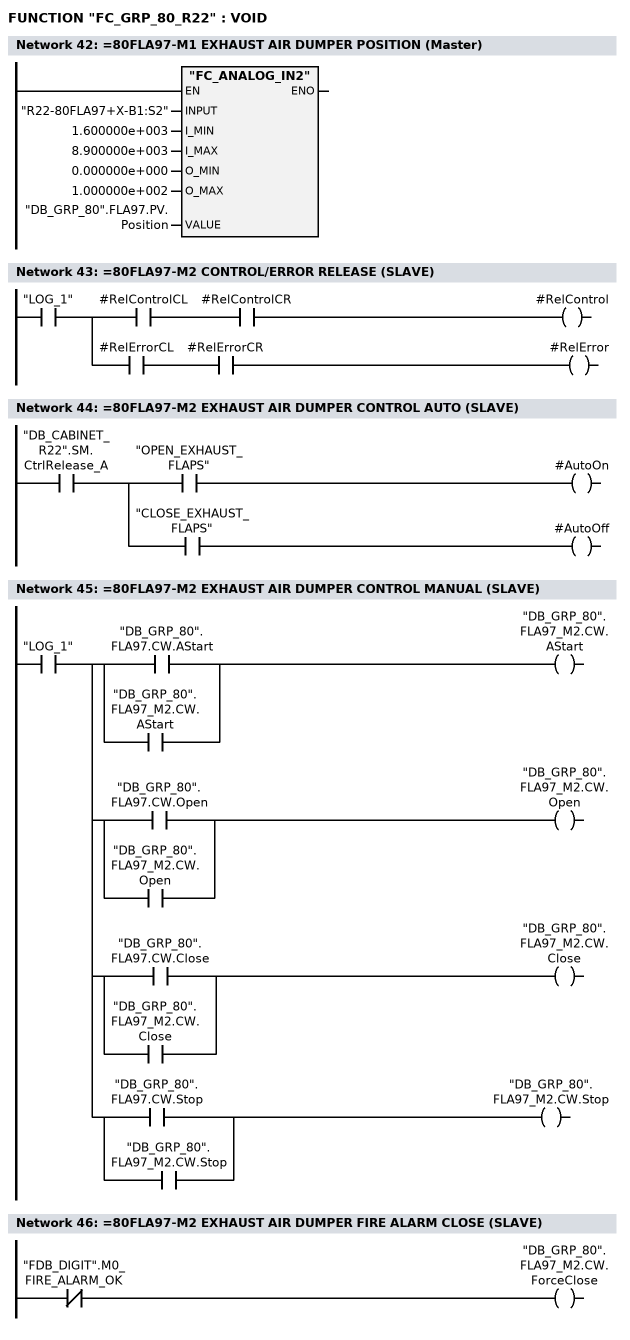
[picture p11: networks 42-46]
      CALL "FC_ANALOG_IN2" (
           INPUT                    := "R22-80FLA97+X-B1:S2",
           I_MIN                    := 1.600000e+003,
           I_MAX                    := 8.900000e+003,
           O_MIN                    := 0.000000e+000,
           O_MAX                    := 1.000000e+002,
           VALUE                    := "DB_GRP_80".FLA97.PV.Position);
      NOP   0;
NETWORK
TITLE ==80FLA97-M2 CONTROL/ERROR RELEASE (SLAVE)

      U     "LOG_1";
      =     L     18.0;
      U     L     18.0;
      U     #RelControlCL;
      U     #RelControlCR;
      =     #RelControl;
      U     L     18.0;
      U     #RelErrorCL;
      U     #RelErrorCR;
      =     #RelError;
NETWORK
TITLE ==80FLA97-M2 EXHAUST AIR DUMPER CONTROL AUTO (SLAVE)

      U     "DB_CABINET_R22".SM.CtrlRelease_A;
      =     L     18.0;
      U     L     18.0;
      U     "OPEN_EXHAUST_FLAPS";
      =     #AutoOn;
      U     L     18.0;
      U     "CLOSE_EXHAUST_FLAPS";
      =     #AutoOff;
NETWORK
TITLE ==80FLA97-M2 EXHAUST AIR DUMPER CONTROL MANUAL (SLAVE)

      U     "LOG_1";
      =     L     18.0;
      U     L     18.0;
      U(    ;
      O     "DB_GRP_80".FLA97.CW.AStart;
      O     "DB_GRP_80".FLA97_M2.CW.AStart;
      )     ;
      =     "DB_GRP_80".FLA97_M2.CW.AStart;
      U     L     18.0;
      U(    ;
      O     "DB_GRP_80".FLA97.CW.Open;
      O     "DB_GRP_80".FLA97_M2.CW.Open;
      )     ;
      =     "DB_GRP_80".FLA97_M2.CW.Open;
      U     L     18.0;
      U(    ;
      O     "DB_GRP_80".FLA97.CW.Close;
      O     "DB_GRP_80".FLA97_M2.CW.Close;
      )     ;
      =     "DB_GRP_80".FLA97_M2.CW.Close;
      U     L     18.0;
      U(    ;
      O     "DB_GRP_80".FLA97.CW.Stop;
      O     "DB_GRP_80".FLA97_M2.CW.Stop;
      )     ;
      =     "DB_GRP_80".FLA97_M2.CW.Stop;
NETWORK
TITLE ==80FLA97-M2 EXHAUST AIR DUMPER FIRE ALARM CLOSE (SLAVE)

      UN    "FDB_DIGIT".M0_FIRE_ALARM_OK;
      =     "DB_GRP_80".FLA97_M2.CW.ForceClose;
NETWORK
TITLE ==80FLA97-M2 EXHAUST AIR DUMPER (SLAVE)

      U     #RelControl;
      =     L     18.0;
      BLD   103;
      U     #RelError;
      =     L     18.1;
      BLD   103;
      U(    ;
      O     "apertura flap";
      O     #AutoOn;
      )     ;
      =     L     18.2;
      BLD   103;
      U(    ;
      O     M     52.1;
      O     #AutoOff;
      )     ;
      UN    "apertura flap";
      =     L     18.3;
      BLD   103;
      U     "LOG_1";
      =     L     18.4;
      BLD   103;
      U(    ;
      U     "R22-80FLA97+X-S1C.1:4";
      U(    ;
      L     "DB_GRP_80".FLA97_M2.PV.Position;
      L     9.500000e+001;
      >R    ;
      )     ;
      L     S5T#10S;
      SE    "T_80FLA97-M2_LS_O";
      NOP   0;
      NOP   0;
      NOP   0;
      U     "T_80FLA97-M2_LS_O";
      )     ;
      =     L     18.5;
      BLD   103;
      U(    ;
      UN    "R22-80FLA97+X-S1C.1:4";
      U(    ;
      L     "DB_GRP_80".FLA97_M2.PV.Position;
      L     2.000000e+000;
      <R    ;
      )     ;
      L     S5T#10S;
      SE    "T_80FLA97-M2_LS_C";
      NOP   0;
      NOP   0;
      NOP   0;
      U     "T_80FLA97-M2_LS_C";
      )     ;
      =     L     18.6;
      BLD   103;
      U     #ErrorConfirm;
      =     L     18.7;
      BLD   103;
      CALL "FC_FLAP" (
           REL_CONTROL              := L     18.0,
           REL_ERROR                := L     18.1,
           CL                       := #CL,
           CR                       := #CR,
           AUTO_OPEN                := L     18.2,
           AUTO_CLOSE               := L     18.3,
           FUSE                     := L     18.4,
           LS_OPEN                  := L     18.5,
           LS_CLOSE                 := L     18.6,
           ERROR_CONFIRM            := L     18.7,
           MAX_RUNTIME              := 200,
           OPEN                     := "R22-80FLA97+X-M2:2",
           CLOSE                    := "R22-80FLA97+X-M2:3",
           DDB                      := "DB_GRP_80".FLA97_M2);
      NOP   0;
NETWORK
TITLE ==80FLA97-M2 EXHAUST AIR DUMPER ERROR/WARNING TO MASTER (SLAVE)

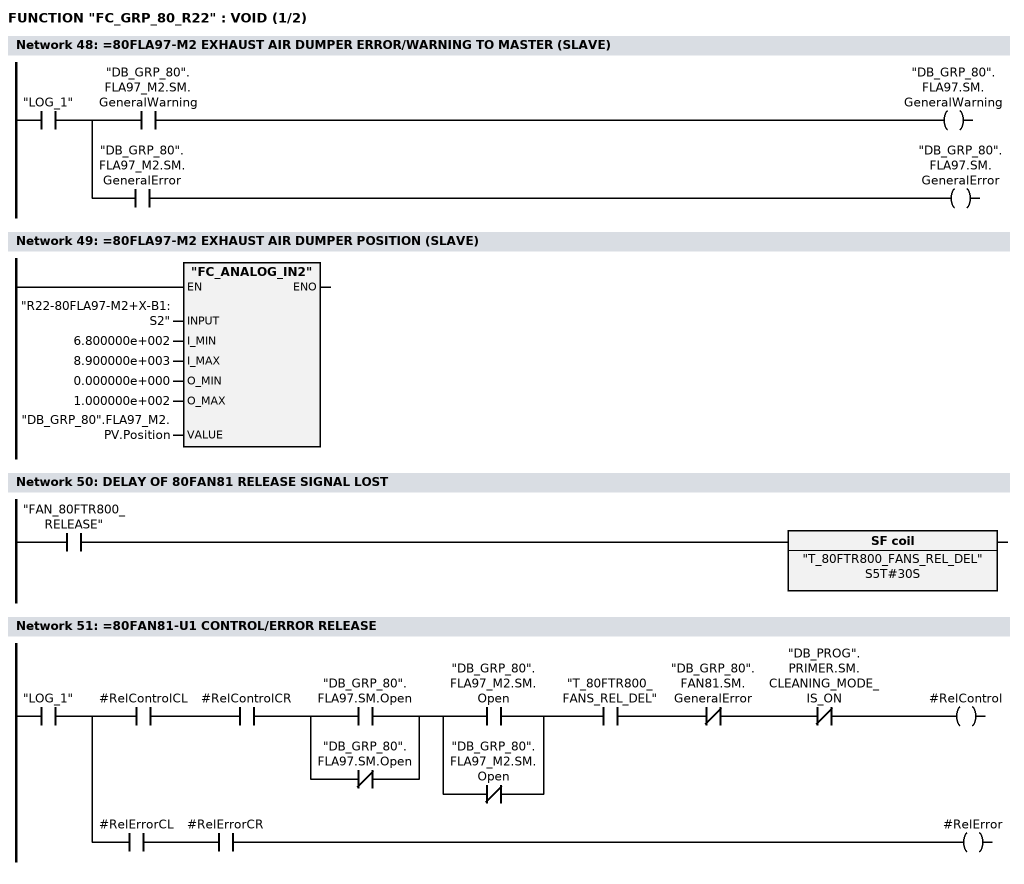
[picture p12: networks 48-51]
      U     "LOG_1";
      =     L     18.0;
      U     L     18.0;
      U     "DB_GRP_80".FLA97_M2.SM.GeneralWarning;
      =     "DB_GRP_80".FLA97.SM.GeneralWarning;
      U     L     18.0;
      U     "DB_GRP_80".FLA97_M2.SM.GeneralError;
      =     "DB_GRP_80".FLA97.SM.GeneralError;
NETWORK
TITLE ==80FLA97-M2 EXHAUST AIR DUMPER POSITION (SLAVE)

      CALL "FC_ANALOG_IN2" (
           INPUT                    := "R22-80FLA97-M2+X-B1:S2",
           I_MIN                    := 6.800000e+002,
           I_MAX                    := 8.900000e+003,
           O_MIN                    := 0.000000e+000,
           O_MAX                    := 1.000000e+002,
           VALUE                    := "DB_GRP_80".FLA97_M2.PV.Position);
      NOP   0;
NETWORK
TITLE =DELAY OF 80FAN81 RELEASE SIGNAL LOST

      U     "FAN_80FTR800_RELEASE";
      L     S5T#30S;
      SA    "T_80FTR800_FANS_REL_DEL";
      NOP   0;
      NOP   0;
      NOP   0;
      NOP   0;
NETWORK
TITLE ==80FAN81-U1 CONTROL/ERROR RELEASE

      U     "LOG_1";
      =     L     18.0;
      U     L     18.0;
      U     #RelControlCL;
      U     #RelControlCR;
      U(    ;
      O     "DB_GRP_80".FLA97.SM.Open;
      ON    "DB_GRP_80".FLA97.SM.Open;
      )     ;
      U(    ;
      O     "DB_GRP_80".FLA97_M2.SM.Open;
      ON    "DB_GRP_80".FLA97_M2.SM.Open;
      )     ;
      U     "T_80FTR800_FANS_REL_DEL";
      UN    "DB_GRP_80".FAN81.SM.GeneralError;
      UN    "DB_PROG".PRIMER.SM.CLEANING_MODE_IS_ON;
      =     #RelControl;
      U     L     18.0;
      U     #RelErrorCL;
      U     #RelErrorCR;
      =     #RelError;
NETWORK
TITLE ==80FAN81-U1 CONTROL SIGNALS

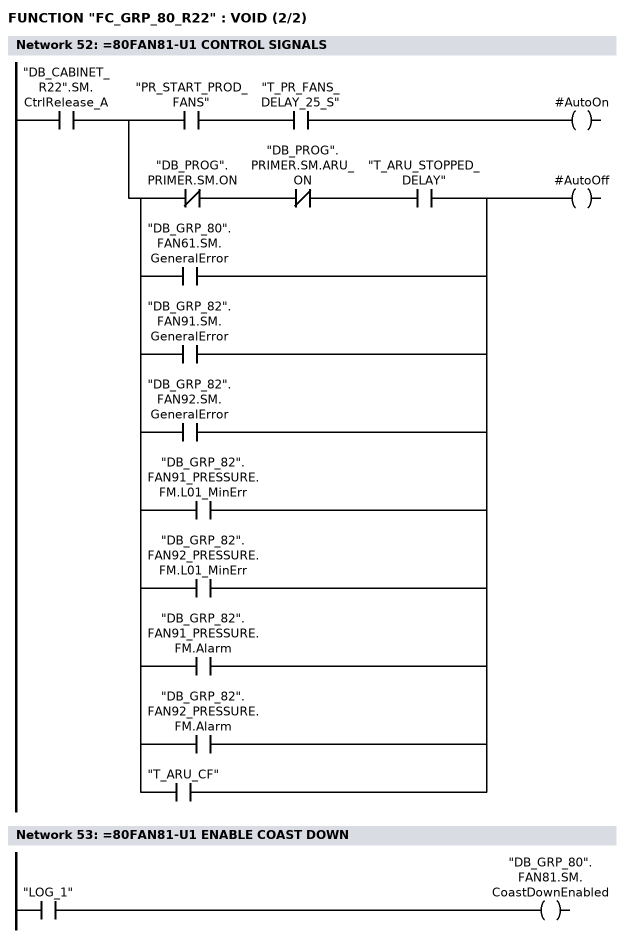
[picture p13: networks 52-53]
      U     "DB_CABINET_R22".SM.CtrlRelease_A;
      =     L     18.0;
      U     L     18.0;
      U     "PR_START_PROD_FANS";
      U     "T_PR_FANS_DELAY_25_S";
      =     #AutoOn;
      U     L     18.0;
      U(    ;
      UN    "DB_PROG".PRIMER.SM.ON;
      UN    "DB_PROG".PRIMER.SM.ARU_ON;
      U     "T_ARU_STOPPED_DELAY";
      O     "DB_GRP_80".FAN61.SM.GeneralError;
      O     "DB_GRP_82".FAN91.SM.GeneralError;
      O     "DB_GRP_82".FAN92.SM.GeneralError;
      O     "DB_GRP_82".FAN91_PRESSURE.FM.L01_MinErr;
      O     "DB_GRP_82".FAN92_PRESSURE.FM.L01_MinErr;
      O     "DB_GRP_82".FAN91_PRESSURE.FM.Alarm;
      O     "DB_GRP_82".FAN92_PRESSURE.FM.Alarm;
      O     "T_ARU_CF";
      )     ;
      =     #AutoOff;
NETWORK
TITLE ==80FAN81-U1 ENABLE COAST DOWN

      U     "LOG_1";
      =     "DB_GRP_80".FAN81.SM.CoastDownEnabled;
NETWORK
TITLE ==80FAN81-U1 DELAY START OF PID CONTROL

      U(    ;
      U     "DB_GRP_80".FAN81.SM.AutomaticMode;
      U     "DB_GRP_80".FAN81.SM.MotorOn;
      U     "DB_GRP_80".FAN81.SM.FreqOK;
      S     "80FAN81_PID_Delay";
      U(    ;
      ON    "DB_GRP_80".FAN81.SM.MotorOn;
      O     "DB_GRP_80".FAN81.SM.ManualMode;
      )     ;
      R     "80FAN81_PID_Delay";
      U     "80FAN81_PID_Delay";
      )     ;
      L     S5T#2M;
      SE    "T_80FAN81_PID_Delay";
      UN    "DB_GRP_80".FAN81.SM.MotorOn;
      R     "T_80FAN81_PID_Delay";
      NOP   0;
      NOP   0;
      NOP   0;
NETWORK
TITLE =80FAN81-U1 PID SETPOINT TRANSFER

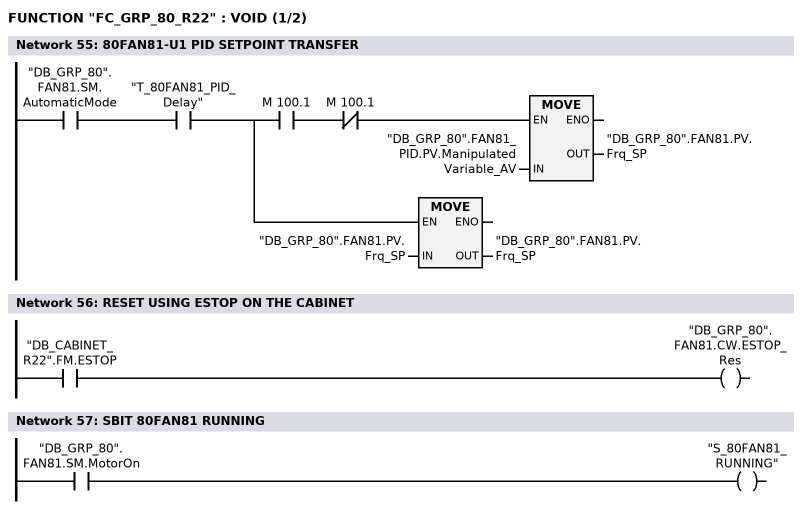
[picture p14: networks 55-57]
      U     "DB_GRP_80".FAN81.SM.AutomaticMode;
      U     "T_80FAN81_PID_Delay";
      =     L     18.0;
      U     L     18.0;
      U     M    100.1;
      UN    M    100.1;
      SPBNB _005;
      L     "DB_GRP_80".FAN81_PID.PV.ManipulatedVariable_AV;
      T     "DB_GRP_80".FAN81.PV.Frq_SP;
_005: NOP   0;
      U     L     18.0;
      SPBNB _006;
      L     "DB_GRP_80".FAN81.PV.Frq_SP;
      T     "DB_GRP_80".FAN81.PV.Frq_SP;
_006: NOP   0;
NETWORK
TITLE =RESET USING ESTOP ON THE CABINET

      U     "DB_CABINET_R22".FM.ESTOP;
      =     "DB_GRP_80".FAN81.CW.ESTOP_Res;
NETWORK
TITLE =SBIT 80FAN81 RUNNING

      U     "DB_GRP_80".FAN81.SM.MotorOn;
      =     "S_80FAN81_RUNNING";
NETWORK
TITLE ==80FAN81-U1 EXHAUST AIR FAN

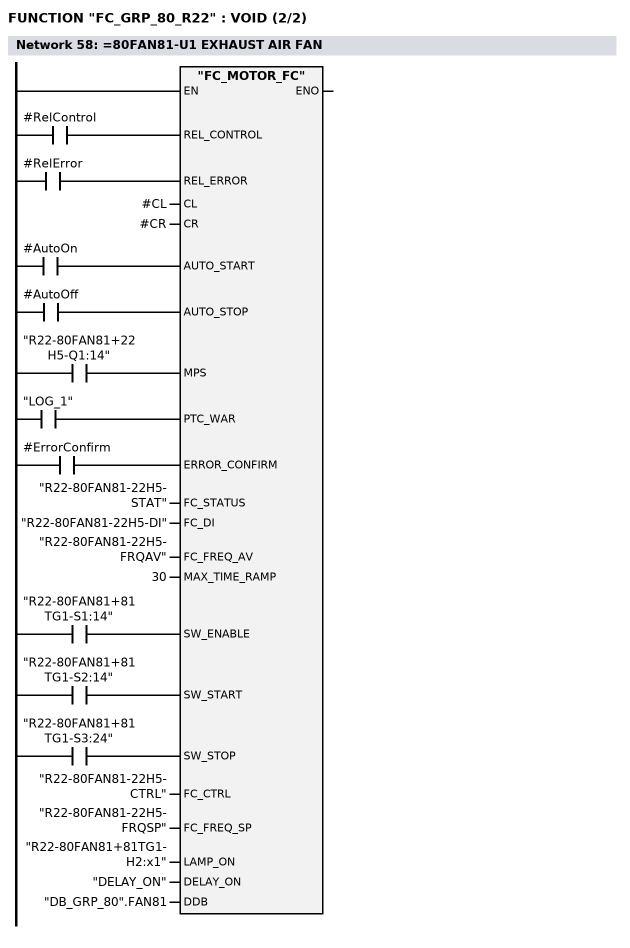
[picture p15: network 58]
      U     #RelControl;
      =     L     18.0;
      BLD   103;
      U     #RelError;
      =     L     18.1;
      BLD   103;
      U     #AutoOn;
      =     L     18.2;
      BLD   103;
      U     #AutoOff;
      =     L     18.3;
      BLD   103;
      U     "R22-80FAN81+22H5-Q1:14";
      =     L     18.4;
      BLD   103;
      U     "LOG_1";
      =     L     18.5;
      BLD   103;
      U     #ErrorConfirm;
      =     L     18.6;
      BLD   103;
      U     "R22-80FAN81+81TG1-S1:14";
      =     L     18.7;
      BLD   103;
      U     "R22-80FAN81+81TG1-S2:14";
      =     L     19.0;
      BLD   103;
      U     "R22-80FAN81+81TG1-S3:24";
      =     L     19.1;
      BLD   103;
      CALL "FC_MOTOR_FC" (
           REL_CONTROL              := L     18.0,
           REL_ERROR                := L     18.1,
           CL                       := #CL,
           CR                       := #CR,
           AUTO_START               := L     18.2,
           AUTO_STOP                := L     18.3,
           MPS                      := L     18.4,
           PTC_WAR                  := L     18.5,
           ERROR_CONFIRM            := L     18.6,
           FC_STATUS                := "R22-80FAN81-22H5-STAT",
           FC_DI                    := "R22-80FAN81-22H5-DI",
           FC_FREQ_AV               := "R22-80FAN81-22H5-FRQAV",
           MAX_TIME_RAMP            := 30,
           SW_ENABLE                := L     18.7,
           SW_START                 := L     19.0,
           SW_STOP                  := L     19.1,
           FC_CTRL                  := "R22-80FAN81-22H5-CTRL",
           FC_FREQ_SP               := "R22-80FAN81-22H5-FRQSP",
           LAMP_ON                  := "R22-80FAN81+81TG1-H2:x1",
           DELAY_ON                 := "DELAY_ON",
           DDB                      := "DB_GRP_80".FAN81);
      NOP   0;
NETWORK
TITLE ==80FAN81-U1 SETPOINT UNREACHABLE FAULT

      U     #ErrorConfirm;
      R     "DB_DIGIT".FM.G80_FAN81_SP_UNREACHABLE;
      U(    ;
      U     #RelError;
      U     "DB_PROG".PRIMER.SM.ON;
      U     "DB_GRP_80".FAN81.SM.MotorOn;
      U(    ;
      U(    ;
      L     "DB_GRP_80".FAN81.PV.Frq_AV;
      L     1.000000e+000;
      <R    ;
      )     ;
      U(    ;
      L     "DB_GRP_80".FAN81_PRESSURE.PV.AV;
      L     "DB_SETPOINTS".ECUBE_80FAN81_SP;
      >R    ;
      )     ;
      O     ;
      U(    ;
      L     "DB_GRP_80".FAN81.PV.Frq_AV;
      L     4.900000e+001;
      >R    ;
      )     ;
      U(    ;
      L     "DB_GRP_80".FAN81_PRESSURE.PV.AV;
      L     "DB_SETPOINTS".ECUBE_80FAN81_SP;
      <R    ;
      )     ;
      )     ;
      L     S5T#3M;
      SE    "T_80FAN81_SP_UNREACHABLE";
      NOP   0;
      NOP   0;
      NOP   0;
      U     "T_80FAN81_SP_UNREACHABLE";
      )     ;
      S     "DB_DIGIT".FM.G80_FAN81_SP_UNREACHABLE;
      NOP   0;
NETWORK
TITLE ==80FAN81-U1 RELEASE ERROR

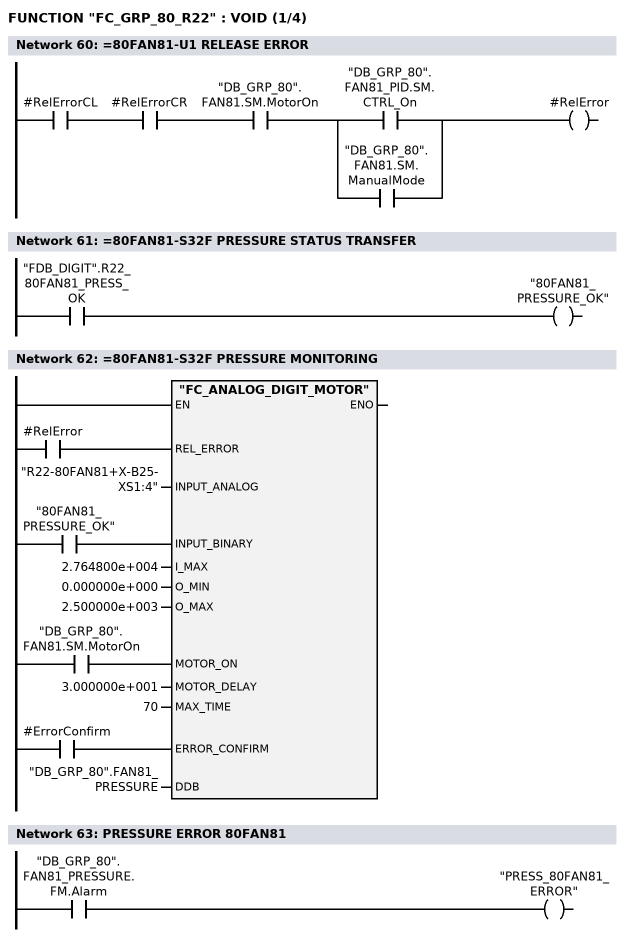
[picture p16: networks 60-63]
      U     #RelErrorCL;
      U     #RelErrorCR;
      U     "DB_GRP_80".FAN81.SM.MotorOn;
      U(    ;
      O     "DB_GRP_80".FAN81_PID.SM.CTRL_On;
      O     "DB_GRP_80".FAN81.SM.ManualMode;
      )     ;
      =     #RelError;
NETWORK
TITLE ==80FAN81-S32F PRESSURE STATUS TRANSFER

      U     "FDB_DIGIT".R22_80FAN81_PRESS_OK;
      =     "80FAN81_PRESSURE_OK";
NETWORK
TITLE ==80FAN81-S32F PRESSURE MONITORING

      U     #RelError;
      =     L     18.0;
      BLD   103;
      U     "80FAN81_PRESSURE_OK";
      =     L     18.1;
      BLD   103;
      U     "DB_GRP_80".FAN81.SM.MotorOn;
      =     L     18.2;
      BLD   103;
      U     #ErrorConfirm;
      =     L     18.3;
      BLD   103;
      CALL "FC_ANALOG_DIGIT_MOTOR" (
           REL_ERROR                := L     18.0,
           INPUT_ANALOG             := "R22-80FAN81+X-B25-XS1:4",
           INPUT_BINARY             := L     18.1,
           I_MAX                    := 2.764800e+004,
           O_MIN                    := 0.000000e+000,
           O_MAX                    := 2.500000e+003,
           MOTOR_ON                 := L     18.2,
           MOTOR_DELAY              := 3.000000e+001,
           MAX_TIME                 := 70,
           ERROR_CONFIRM            := L     18.3,
           DDB                      := "DB_GRP_80".FAN81_PRESSURE);
      NOP   0;
NETWORK
TITLE =PRESSURE ERROR 80FAN81

      U     "DB_GRP_80".FAN81_PRESSURE.FM.Alarm;
      =     "PRESS_80FAN81_ERROR";
NETWORK
TITLE ==80FAN81-U1 LIMITS ACCORDING TO SETPOINT

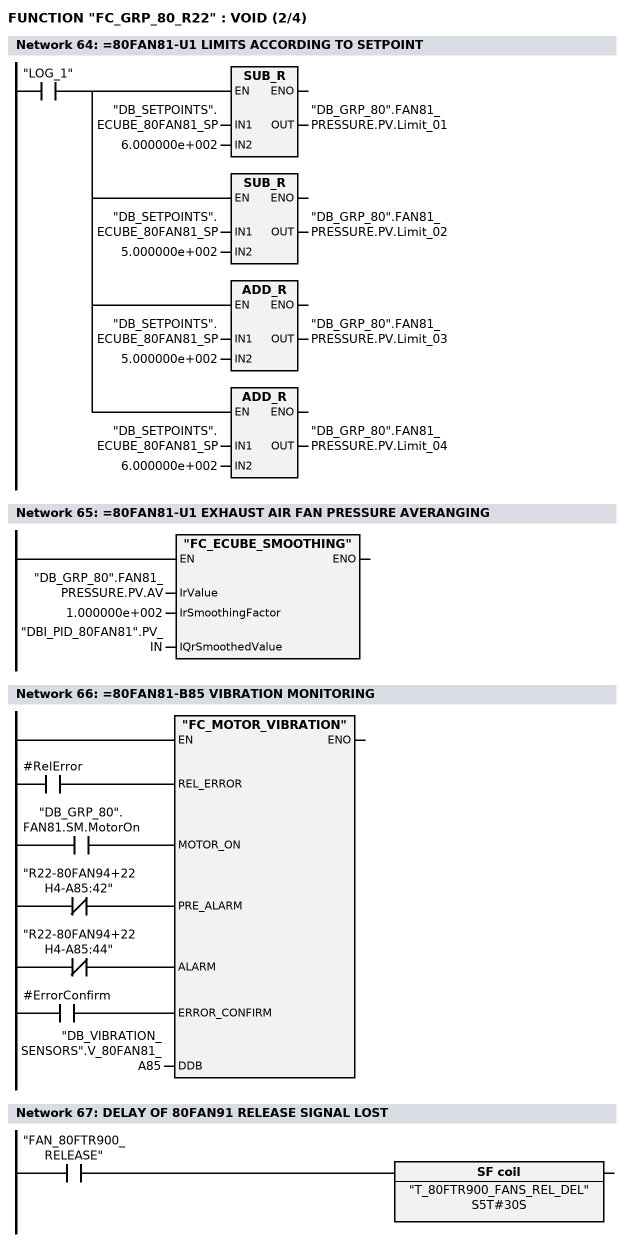
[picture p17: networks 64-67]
      U     "LOG_1";
      =     L     18.0;
      U     L     18.0;
      SPBNB _007;
      L     "DB_SETPOINTS".ECUBE_80FAN81_SP;
      L     6.000000e+002;
      -R    ;
      T     "DB_GRP_80".FAN81_PRESSURE.PV.Limit_01;
_007: NOP   0;
      U     L     18.0;
      SPBNB _008;
      L     "DB_SETPOINTS".ECUBE_80FAN81_SP;
      L     5.000000e+002;
      -R    ;
      T     "DB_GRP_80".FAN81_PRESSURE.PV.Limit_02;
_008: NOP   0;
      U     L     18.0;
      SPBNB _009;
      L     "DB_SETPOINTS".ECUBE_80FAN81_SP;
      L     5.000000e+002;
      +R    ;
      T     "DB_GRP_80".FAN81_PRESSURE.PV.Limit_03;
_009: NOP   0;
      U     L     18.0;
      SPBNB _00a;
      L     "DB_SETPOINTS".ECUBE_80FAN81_SP;
      L     6.000000e+002;
      +R    ;
      T     "DB_GRP_80".FAN81_PRESSURE.PV.Limit_04;
_00a: NOP   0;
NETWORK
TITLE ==80FAN81-U1 EXHAUST AIR FAN PRESSURE AVERANGING

      CALL "FC_ECUBE_SMOOTHING" (
           IrValue                  := "DB_GRP_80".FAN81_PRESSURE.PV.AV,
           IrSmoothingFactor        := 1.000000e+002,
           IQrSmoothedValue         := "DBI_PID_80FAN81".PV_IN);
      NOP   0;
NETWORK
TITLE ==80FAN81-B85 VIBRATION MONITORING

      U     #RelError;
      =     L     18.0;
      BLD   103;
      U     "DB_GRP_80".FAN81.SM.MotorOn;
      =     L     18.1;
      BLD   103;
      UN    "R22-80FAN94+22H4-A85:42";
      =     L     18.2;
      BLD   103;
      UN    "R22-80FAN94+22H4-A85:44";
      =     L     18.3;
      BLD   103;
      U     #ErrorConfirm;
      =     L     18.4;
      BLD   103;
      CALL "FC_MOTOR_VIBRATION" (
           REL_ERROR                := L     18.0,
           MOTOR_ON                 := L     18.1,
           PRE_ALARM                := L     18.2,
           ALARM                    := L     18.3,
           ERROR_CONFIRM            := L     18.4,
           DDB                      := "DB_VIBRATION_SENSORS".V_80FAN81_A85);
      NOP   0;
NETWORK
TITLE =DELAY OF 80FAN91 RELEASE SIGNAL LOST

      U     "FAN_80FTR900_RELEASE";
      L     S5T#30S;
      SA    "T_80FTR900_FANS_REL_DEL";
      NOP   0;
      NOP   0;
      NOP   0;
      NOP   0;
NETWORK
TITLE ==80FAN91-U1 CONTROL/ERROR RELEASE

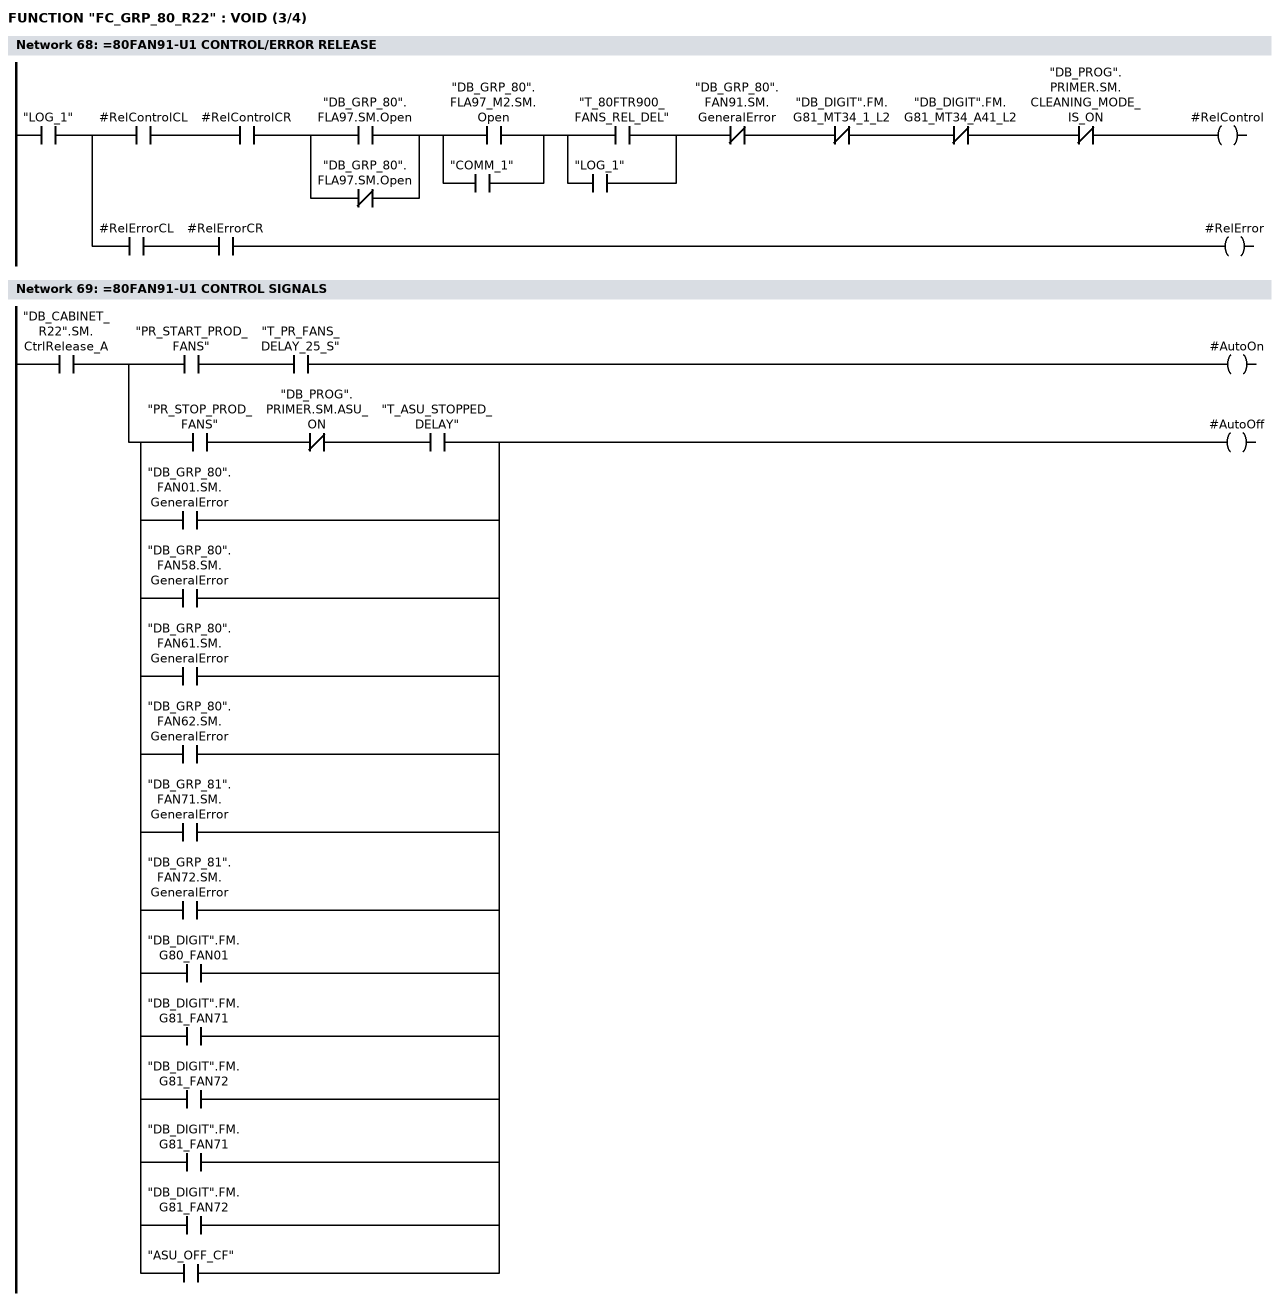
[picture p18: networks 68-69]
      U     "LOG_1";
      =     L     18.0;
      U     L     18.0;
      U     #RelControlCL;
      U     #RelControlCR;
      U(    ;
      O     "DB_GRP_80".FLA97.SM.Open;
      ON    "DB_GRP_80".FLA97.SM.Open;
      )     ;
      U(    ;
      O     "DB_GRP_80".FLA97_M2.SM.Open;
      O     "COMM_1";
      )     ;
      U(    ;
      O     "T_80FTR900_FANS_REL_DEL";
      O     "LOG_1";
      )     ;
      UN    "DB_GRP_80".FAN91.SM.GeneralError;
      UN    "DB_DIGIT".FM.G81_MT34_1_L2;
      UN    "DB_DIGIT".FM.G81_MT34_A41_L2;
      UN    "DB_PROG".PRIMER.SM.CLEANING_MODE_IS_ON;
      =     #RelControl;
      U     L     18.0;
      U     #RelErrorCL;
      U     #RelErrorCR;
      =     #RelError;
NETWORK
TITLE ==80FAN91-U1 CONTROL SIGNALS

      U     "DB_CABINET_R22".SM.CtrlRelease_A;
      =     L     18.0;
      U     L     18.0;
      U     "PR_START_PROD_FANS";
      U     "T_PR_FANS_DELAY_25_S";
      =     #AutoOn;
      U     L     18.0;
      U(    ;
      U     "PR_STOP_PROD_FANS";
      UN    "DB_PROG".PRIMER.SM.ASU_ON;
      U     "T_ASU_STOPPED_DELAY";
      O     "DB_GRP_80".FAN01.SM.GeneralError;
      O     "DB_GRP_80".FAN58.SM.GeneralError;
      O     "DB_GRP_80".FAN61.SM.GeneralError;
      O     "DB_GRP_80".FAN62.SM.GeneralError;
      O     "DB_GRP_81".FAN71.SM.GeneralError;
      O     "DB_GRP_81".FAN72.SM.GeneralError;
      O     "DB_DIGIT".FM.G80_FAN01;
      O     "DB_DIGIT".FM.G81_FAN71;
      O     "DB_DIGIT".FM.G81_FAN72;
      O     "DB_DIGIT".FM.G81_FAN71;
      O     "DB_DIGIT".FM.G81_FAN72;
      O     "ASU_OFF_CF";
      )     ;
      =     #AutoOff;
NETWORK
TITLE ==80FAN91-U1 ENABLE COAST DOWN

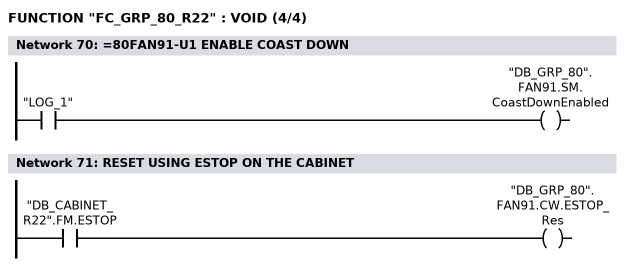
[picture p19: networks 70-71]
      U     "LOG_1";
      =     "DB_GRP_80".FAN91.SM.CoastDownEnabled;
NETWORK
TITLE =RESET USING ESTOP ON THE CABINET

      U     "DB_CABINET_R22".FM.ESTOP;
      =     "DB_GRP_80".FAN91.CW.ESTOP_Res;
NETWORK
TITLE ==80FAN91-U1 DELAY START OF PID CONTROL

      U(    ;
      U     "DB_GRP_80".FAN91.SM.AutomaticMode;
      U     "DB_GRP_80".FAN91.SM.MotorOn;
      U     "DB_GRP_80".FAN91.SM.FreqOK;
      S     "80FAN91_PID_Delay";
      U(    ;
      ON    "DB_GRP_80".FAN91.SM.MotorOn;
      O     "DB_GRP_80".FAN91.SM.ManualMode;
      )     ;
      R     "80FAN91_PID_Delay";
      U     "80FAN91_PID_Delay";
      )     ;
      L     S5T#2M;
      SE    "T_80FAN91_PID_Delay";
      UN    "DB_GRP_80".FAN91.SM.MotorOn;
      R     "T_80FAN91_PID_Delay";
      NOP   0;
      NOP   0;
      NOP   0;
NETWORK
TITLE =80FAN91-U1 PID CONTROL SETPOINT

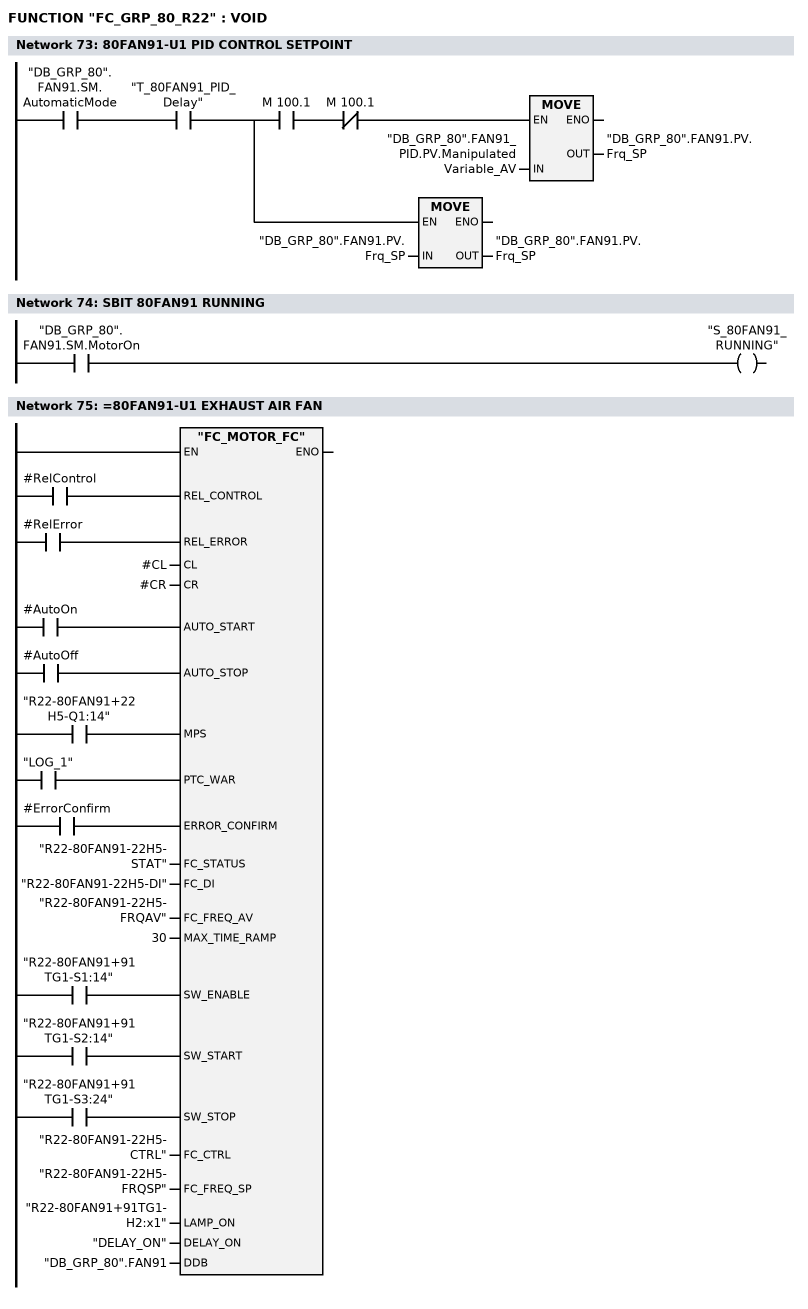
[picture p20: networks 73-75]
      U     "DB_GRP_80".FAN91.SM.AutomaticMode;
      U     "T_80FAN91_PID_Delay";
      =     L     18.0;
      U     L     18.0;
      U     M    100.1;
      UN    M    100.1;
      SPBNB _00b;
      L     "DB_GRP_80".FAN91_PID.PV.ManipulatedVariable_AV;
      T     "DB_GRP_80".FAN91.PV.Frq_SP;
_00b: NOP   0;
      U     L     18.0;
      SPBNB _00c;
      L     "DB_GRP_80".FAN91.PV.Frq_SP;
      T     "DB_GRP_80".FAN91.PV.Frq_SP;
_00c: NOP   0;
NETWORK
TITLE =SBIT 80FAN91 RUNNING

      U     "DB_GRP_80".FAN91.SM.MotorOn;
      =     "S_80FAN91_RUNNING";
NETWORK
TITLE ==80FAN91-U1 EXHAUST AIR FAN

      U     #RelControl;
      =     L     18.0;
      BLD   103;
      U     #RelError;
      =     L     18.1;
      BLD   103;
      U     #AutoOn;
      =     L     18.2;
      BLD   103;
      U     #AutoOff;
      =     L     18.3;
      BLD   103;
      U     "R22-80FAN91+22H5-Q1:14";
      =     L     18.4;
      BLD   103;
      U     "LOG_1";
      =     L     18.5;
      BLD   103;
      U     #ErrorConfirm;
      =     L     18.6;
      BLD   103;
      U     "R22-80FAN91+91TG1-S1:14";
      =     L     18.7;
      BLD   103;
      U     "R22-80FAN91+91TG1-S2:14";
      =     L     19.0;
      BLD   103;
      U     "R22-80FAN91+91TG1-S3:24";
      =     L     19.1;
      BLD   103;
      CALL "FC_MOTOR_FC" (
           REL_CONTROL              := L     18.0,
           REL_ERROR                := L     18.1,
           CL                       := #CL,
           CR                       := #CR,
           AUTO_START               := L     18.2,
           AUTO_STOP                := L     18.3,
           MPS                      := L     18.4,
           PTC_WAR                  := L     18.5,
           ERROR_CONFIRM            := L     18.6,
           FC_STATUS                := "R22-80FAN91-22H5-STAT",
           FC_DI                    := "R22-80FAN91-22H5-DI",
           FC_FREQ_AV               := "R22-80FAN91-22H5-FRQAV",
           MAX_TIME_RAMP            := 30,
           SW_ENABLE                := L     18.7,
           SW_START                 := L     19.0,
           SW_STOP                  := L     19.1,
           FC_CTRL                  := "R22-80FAN91-22H5-CTRL",
           FC_FREQ_SP               := "R22-80FAN91-22H5-FRQSP",
           LAMP_ON                  := "R22-80FAN91+91TG1-H2:x1",
           DELAY_ON                 := "DELAY_ON",
           DDB                      := "DB_GRP_80".FAN91);
      NOP   0;
NETWORK
TITLE ==80FAN91-U1 SETPOINT UNREACHABLE FAULT

      U     #ErrorConfirm;
      R     "DB_DIGIT".FM.G80_FAN91_SP_UNREACHABLE;
      U(    ;
      U     #RelError;
      U     "DB_PROG".PRIMER.SM.ON;
      U     "DB_GRP_80".FAN91.SM.MotorOn;
      U(    ;
      U(    ;
      L     "DB_GRP_80".FAN91.PV.Frq_AV;
      L     1.000000e+000;
      <R    ;
      )     ;
      U(    ;
      L     "DB_GRP_80".FAN91_PRESSURE.PV.AV;
      L     "DB_SETPOINTS".ECUBE_80FAN91_SP;
      >R    ;
      )     ;
      O     ;
      U(    ;
      L     "DB_GRP_80".FAN91.PV.Frq_AV;
      L     4.900000e+001;
      >R    ;
      )     ;
      U(    ;
      L     "DB_GRP_80".FAN91_PRESSURE.PV.AV;
      L     "DB_SETPOINTS".ECUBE_80FAN91_SP;
      <R    ;
      )     ;
      )     ;
      L     S5T#3M;
      SE    "T_80FAN91_SP_UNREACHABLE";
      NOP   0;
      NOP   0;
      NOP   0;
      U     "T_80FAN91_SP_UNREACHABLE";
      )     ;
      S     "DB_DIGIT".FM.G80_FAN91_SP_UNREACHABLE;
      NOP   0;
NETWORK
TITLE ==80FAN91-U1 RELEASE ERROR

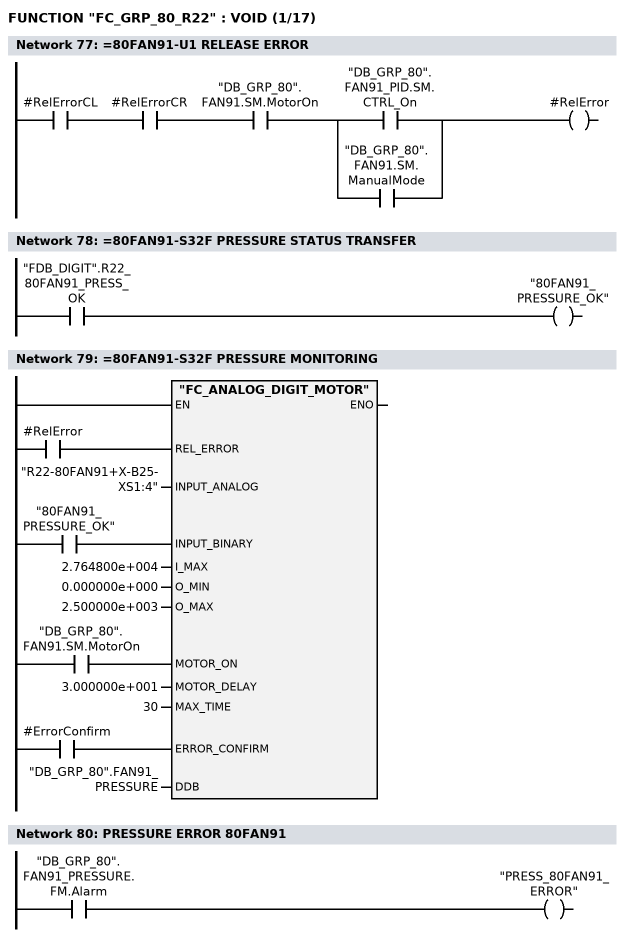
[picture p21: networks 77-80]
      U     #RelErrorCL;
      U     #RelErrorCR;
      U     "DB_GRP_80".FAN91.SM.MotorOn;
      U(    ;
      O     "DB_GRP_80".FAN91_PID.SM.CTRL_On;
      O     "DB_GRP_80".FAN91.SM.ManualMode;
      )     ;
      =     #RelError;
NETWORK
TITLE ==80FAN91-S32F PRESSURE STATUS TRANSFER

      U     "FDB_DIGIT".R22_80FAN91_PRESS_OK;
      =     "80FAN91_PRESSURE_OK";
NETWORK
TITLE ==80FAN91-S32F PRESSURE MONITORING

      U     #RelError;
      =     L     18.0;
      BLD   103;
      U     "80FAN91_PRESSURE_OK";
      =     L     18.1;
      BLD   103;
      U     "DB_GRP_80".FAN91.SM.MotorOn;
      =     L     18.2;
      BLD   103;
      U     #ErrorConfirm;
      =     L     18.3;
      BLD   103;
      CALL "FC_ANALOG_DIGIT_MOTOR" (
           REL_ERROR                := L     18.0,
           INPUT_ANALOG             := "R22-80FAN91+X-B25-XS1:4",
           INPUT_BINARY             := L     18.1,
           I_MAX                    := 2.764800e+004,
           O_MIN                    := 0.000000e+000,
           O_MAX                    := 2.500000e+003,
           MOTOR_ON                 := L     18.2,
           MOTOR_DELAY              := 3.000000e+001,
           MAX_TIME                 := 30,
           ERROR_CONFIRM            := L     18.3,
           DDB                      := "DB_GRP_80".FAN91_PRESSURE);
      NOP   0;
NETWORK
TITLE =PRESSURE ERROR 80FAN91

      U     "DB_GRP_80".FAN91_PRESSURE.FM.Alarm;
      =     "PRESS_80FAN91_ERROR";
NETWORK
TITLE ==80FAN91-U1 LIMITS ACCORDING TO SETPOINT

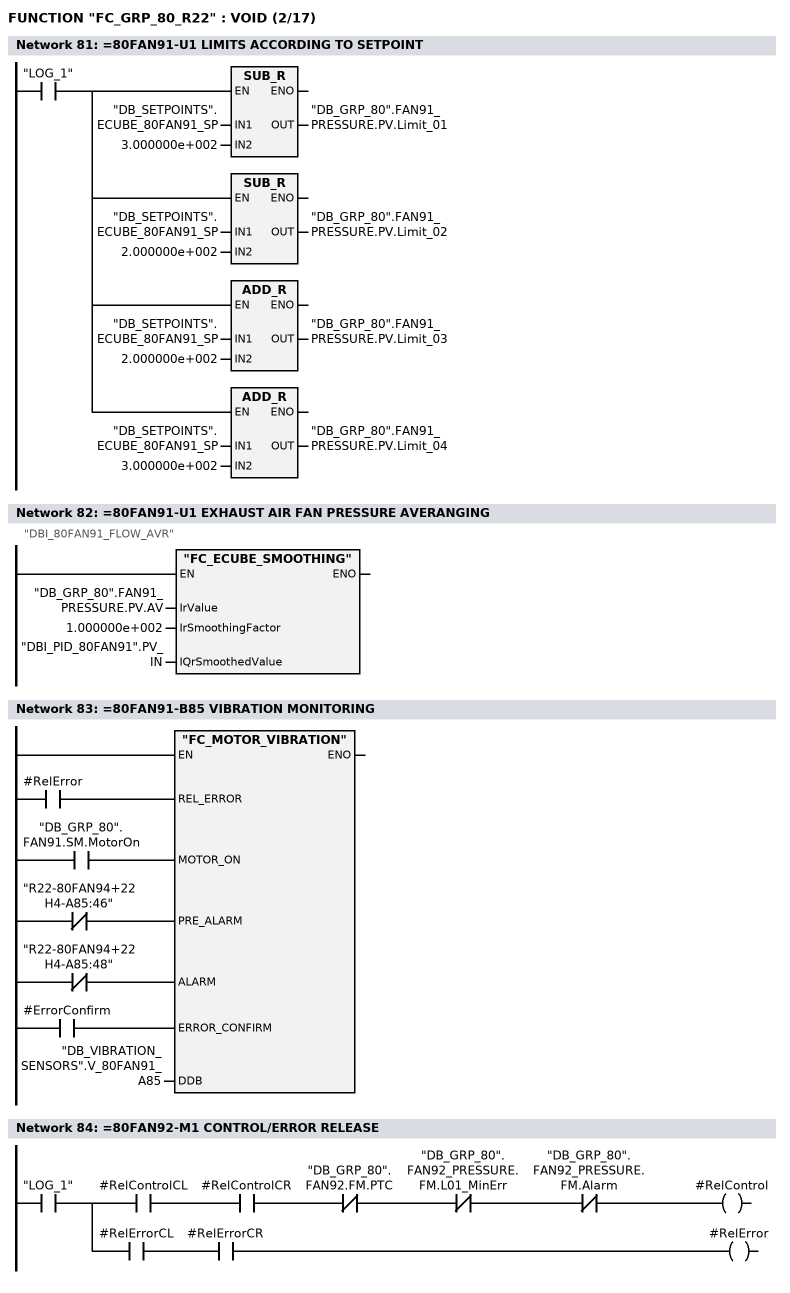
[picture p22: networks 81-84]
      U     "LOG_1";
      =     L     18.0;
      U     L     18.0;
      SPBNB _00d;
      L     "DB_SETPOINTS".ECUBE_80FAN91_SP;
      L     3.000000e+002;
      -R    ;
      T     "DB_GRP_80".FAN91_PRESSURE.PV.Limit_01;
_00d: NOP   0;
      U     L     18.0;
      SPBNB _00e;
      L     "DB_SETPOINTS".ECUBE_80FAN91_SP;
      L     2.000000e+002;
      -R    ;
      T     "DB_GRP_80".FAN91_PRESSURE.PV.Limit_02;
_00e: NOP   0;
      U     L     18.0;
      SPBNB _00f;
      L     "DB_SETPOINTS".ECUBE_80FAN91_SP;
      L     2.000000e+002;
      +R    ;
      T     "DB_GRP_80".FAN91_PRESSURE.PV.Limit_03;
_00f: NOP   0;
      U     L     18.0;
      SPBNB _010;
      L     "DB_SETPOINTS".ECUBE_80FAN91_SP;
      L     3.000000e+002;
      +R    ;
      T     "DB_GRP_80".FAN91_PRESSURE.PV.Limit_04;
_010: NOP   0;
NETWORK
TITLE ==80FAN91-U1 EXHAUST AIR FAN PRESSURE AVERANGING
//"DBI_80FAN91_FLOW_AVR"
      CALL "FC_ECUBE_SMOOTHING" (
           IrValue                  := "DB_GRP_80".FAN91_PRESSURE.PV.AV,
           IrSmoothingFactor        := 1.000000e+002,
           IQrSmoothedValue         := "DBI_PID_80FAN91".PV_IN);
      NOP   0;
NETWORK
TITLE ==80FAN91-B85 VIBRATION MONITORING

      U     #RelError;
      =     L     18.0;
      BLD   103;
      U     "DB_GRP_80".FAN91.SM.MotorOn;
      =     L     18.1;
      BLD   103;
      UN    "R22-80FAN94+22H4-A85:46";
      =     L     18.2;
      BLD   103;
      UN    "R22-80FAN94+22H4-A85:48";
      =     L     18.3;
      BLD   103;
      U     #ErrorConfirm;
      =     L     18.4;
      BLD   103;
      CALL "FC_MOTOR_VIBRATION" (
           REL_ERROR                := L     18.0,
           MOTOR_ON                 := L     18.1,
           PRE_ALARM                := L     18.2,
           ALARM                    := L     18.3,
           ERROR_CONFIRM            := L     18.4,
           DDB                      := "DB_VIBRATION_SENSORS".V_80FAN91_A85);
      NOP   0;
NETWORK
TITLE ==80FAN92-M1 CONTROL/ERROR RELEASE

      U     "LOG_1";
      =     L     18.0;
      U     L     18.0;
      U     #RelControlCL;
      U     #RelControlCR;
      UN    "DB_GRP_80".FAN92.FM.PTC;
      UN    "DB_GRP_80".FAN92_PRESSURE.FM.L01_MinErr;
      UN    "DB_GRP_80".FAN92_PRESSURE.FM.Alarm;
      =     #RelControl;
      U     L     18.0;
      U     #RelErrorCL;
      U     #RelErrorCR;
      =     #RelError;
NETWORK
TITLE ==80FAN92-M1 CONTROL SIGNALS

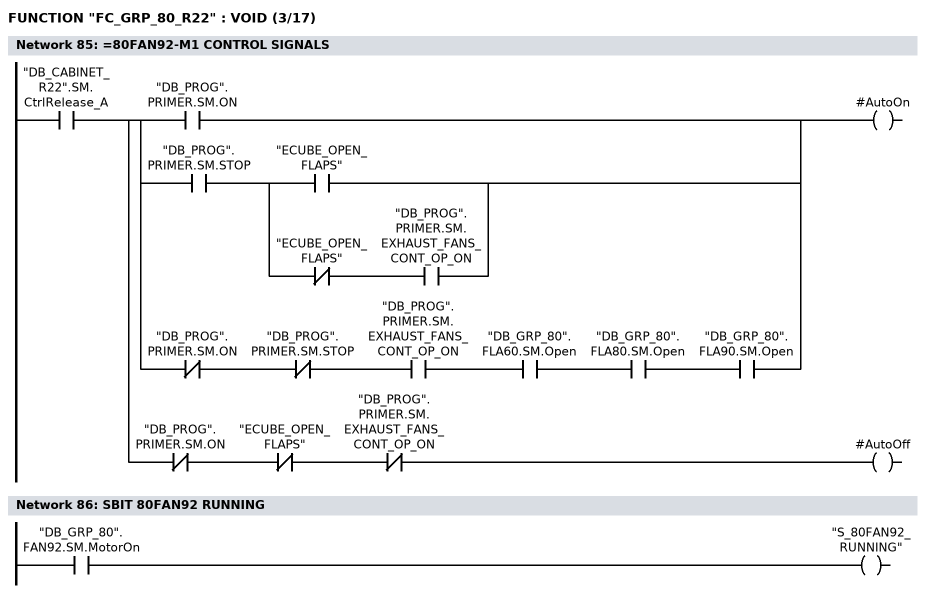
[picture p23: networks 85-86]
      U     "DB_CABINET_R22".SM.CtrlRelease_A;
      =     L     18.0;
      U     L     18.0;
      U(    ;
      O     "DB_PROG".PRIMER.SM.ON;
      O     ;
      U     "DB_PROG".PRIMER.SM.STOP;
      U(    ;
      O     "ECUBE_OPEN_FLAPS";
      O     ;
      UN    "ECUBE_OPEN_FLAPS";
      U     "DB_PROG".PRIMER.SM.EXHAUST_FANS_CONT_OP_ON;
      )     ;
      O     ;
      UN    "DB_PROG".PRIMER.SM.ON;
      UN    "DB_PROG".PRIMER.SM.STOP;
      U     "DB_PROG".PRIMER.SM.EXHAUST_FANS_CONT_OP_ON;
      U     "DB_GRP_80".FLA60.SM.Open;
      U     "DB_GRP_80".FLA80.SM.Open;
      U     "DB_GRP_80".FLA90.SM.Open;
      )     ;
      =     #AutoOn;
      U     L     18.0;
      UN    "DB_PROG".PRIMER.SM.ON;
      UN    "ECUBE_OPEN_FLAPS";
      UN    "DB_PROG".PRIMER.SM.EXHAUST_FANS_CONT_OP_ON;
      =     #AutoOff;
NETWORK
TITLE =SBIT 80FAN92 RUNNING

      U     "DB_GRP_80".FAN92.SM.MotorOn;
      =     "S_80FAN92_RUNNING";
NETWORK
TITLE ==80FAN92-M1 EXHAUST AIR FAN

      U     #RelControl;
      =     L     18.0;
      BLD   103;
      U     #RelError;
      =     L     18.1;
      BLD   103;
      U     #AutoOn;
      =     L     18.2;
      BLD   103;
      U     #AutoOff;
      =     L     18.3;
      BLD   103;
      U     "R22-80FAN92+22H3-Q1:14";
      =     L     18.4;
      BLD   103;
      U     "R22-80FAN92+22H3-K1:14";
      =     L     18.5;
      BLD   103;
      U     "R22-80FAN92+22H3-KBB1:96";
      =     L     18.6;
      BLD   103;
      U     "R22-80FAN92+22H3-WS1:14";
      =     L     18.7;
      BLD   103;
      U     #ErrorConfirm;
      =     L     19.0;
      BLD   103;
      U     "R22-80FAN92+92TG1-S1:14";
      =     L     19.1;
      BLD   103;
      U     "R22-80FAN92+92TG1-S2:14";
      =     L     19.2;
      BLD   103;
      U     "R22-80FAN92+92TG1-S3:24";
      =     L     19.3;
      BLD   103;
      CALL "FC_MOTOR" (
           REL_CONTROL              := L     18.0,
           REL_ERROR                := L     18.1,
           CL                       := #CL,
           CR                       := #CR,
           AUTO_START               := L     18.2,
           AUTO_STOP                := L     18.3,
           MPS                      := L     18.4,
           RM                       := L     18.5,
           PTC                      := L     18.6,
           RS                       := L     18.7,
           ERROR_CONFIRM            := L     19.0,
           SW_ENABLE                := L     19.1,
           SW_START                 := L     19.2,
           SW_STOP                  := L     19.3,
           LAMP_ON                  := "R22-80FAN92+92TG1-H2:x1",
           DELAY_ON                 := "DELAY_ON",
           MOTOR_ON                 := "R22-80FAN92+22H3-K1:A1",
           DDB                      := "DB_GRP_80".FAN92);
      NOP   0;
NETWORK
TITLE ==80FAN92-S32F PRESSURE STATUS TRANSFER

      U     "FDB_DIGIT".R22_80FAN92_PRESS_OK;
      =     "80FAN92_PRESSURE_OK";
NETWORK
TITLE ==80FAN92-S32F PRESSURE MONITORING

      U     #RelError;
      =     L     18.0;
      BLD   103;
      U     "80FAN92_PRESSURE_OK";
      =     L     18.1;
      BLD   103;
      U     "DB_GRP_80".FAN92.SM.MotorOn;
      =     L     18.2;
      BLD   103;
      U     #ErrorConfirm;
      =     L     18.3;
      BLD   103;
      CALL "FC_ANALOG_DIGIT_MOTOR" (
           REL_ERROR                := L     18.0,
           INPUT_ANALOG             := "R22-80FAN92+X-B32F-XS1:4",
           INPUT_BINARY             := L     18.1,
           I_MAX                    := 2.764800e+004,
           O_MIN                    := 0.000000e+000,
           O_MAX                    := 2.500000e+003,
           MOTOR_ON                 := L     18.2,
           MOTOR_DELAY              := 3.000000e+001,
           MAX_TIME                 := 30,
           ERROR_CONFIRM            := L     18.3,
           DDB                      := "DB_GRP_80".FAN92_PRESSURE);
      NOP   0;
NETWORK
TITLE =PRESSURE ERROR 80FAN92

      U     "DB_GRP_80".FAN92_PRESSURE.FM.Alarm;
      =     "PRESS_80FAN92_ERROR";
NETWORK
TITLE ==80FAN93-M1 CONTROL/ERROR RELEASE

      U     "LOG_1";
      =     L     18.0;
      U     L     18.0;
      U     #RelControlCL;
      U     #RelControlCR;
      UN    "DB_GRP_80".FAN93.FM.PTC;
      UN    "DB_GRP_80".FAN93_PRESSURE.FM.L01_MinErr;
      UN    "DB_GRP_80".FAN93_PRESSURE.FM.Alarm;
      =     #RelControl;
      U     L     18.0;
      U     #RelErrorCL;
      U     #RelErrorCR;
      =     #RelError;
NETWORK
TITLE ==80FAN93-M1 CONTROL SIGNALS

      U     "DB_CABINET_R22".SM.CtrlRelease_A;
      =     L     18.0;
      U     L     18.0;
      U(    ;
      O     "DB_PROG".PRIMER.SM.ON;
      O     ;
      U     "DB_PROG".PRIMER.SM.STOP;
      U(    ;
      O     "ECUBE_OPEN_FLAPS";
      O     ;
      UN    "ECUBE_OPEN_FLAPS";
      U     "DB_PROG".PRIMER.SM.EXHAUST_FANS_CONT_OP_ON;
      )     ;
      O     ;
      UN    "DB_PROG".PRIMER.SM.ON;
      UN    "DB_PROG".PRIMER.SM.STOP;
      U     "DB_PROG".PRIMER.SM.EXHAUST_FANS_CONT_OP_ON;
      U     "DB_GRP_80".FLA60.SM.Open;
      U     "DB_GRP_80".FLA80.SM.Open;
      U     "DB_GRP_80".FLA90.SM.Open;
      )     ;
      =     #AutoOn;
      U     L     18.0;
      UN    "DB_PROG".PRIMER.SM.ON;
      UN    "ECUBE_OPEN_FLAPS";
      UN    "DB_PROG".PRIMER.SM.EXHAUST_FANS_CONT_OP_ON;
      =     #AutoOff;
NETWORK
TITLE =SBIT 80FAN93 RUNNING

      U     "DB_GRP_80".FAN93.SM.MotorOn;
      =     "S_80FAN93_RUNNING";
NETWORK
TITLE ==80FAN93-M1 EXHAUST AIR FAN

      U     #RelControl;
      =     L     18.0;
      BLD   103;
      U     #RelError;
      =     L     18.1;
      BLD   103;
      U     #AutoOn;
      =     L     18.2;
      BLD   103;
      U     #AutoOff;
      =     L     18.3;
      BLD   103;
      U     "R22-80FAN93+22H3-Q1:14";
      =     L     18.4;
      BLD   103;
      U     "R22-80FAN93+22H3-K1:14";
      =     L     18.5;
      BLD   103;
      U     "R22-80FAN93+22H3-KBB1:96";
      =     L     18.6;
      BLD   103;
      U     "R22-80FAN93+22H3-WS1:14";
      =     L     18.7;
      BLD   103;
      U     #ErrorConfirm;
      =     L     19.0;
      BLD   103;
      U     "R22-80FAN93+93TG1-S1:14";
      =     L     19.1;
      BLD   103;
      U     "R22-80FAN93+93TG1-S2:14";
      =     L     19.2;
      BLD   103;
      U     "R22-80FAN93+93TG1-S3:24";
      =     L     19.3;
      BLD   103;
      CALL "FC_MOTOR" (
           REL_CONTROL              := L     18.0,
           REL_ERROR                := L     18.1,
           CL                       := #CL,
           CR                       := #CR,
           AUTO_START               := L     18.2,
           AUTO_STOP                := L     18.3,
           MPS                      := L     18.4,
           RM                       := L     18.5,
           PTC                      := L     18.6,
           RS                       := L     18.7,
           ERROR_CONFIRM            := L     19.0,
           SW_ENABLE                := L     19.1,
           SW_START                 := L     19.2,
           SW_STOP                  := L     19.3,
           LAMP_ON                  := "R22-80FAN93+93TG1-H2:x1",
           DELAY_ON                 := "DELAY_ON",
           MOTOR_ON                 := "R22-80FAN93+22H3-K1:A1",
           DDB                      := "DB_GRP_80".FAN93);
      NOP   0;
NETWORK
TITLE ==80FAN93-S32F PRESSURE STATUS TRANSFER

      U     "FDB_DIGIT".R22_80FAN93_PRESS_OK;
      =     "80FAN93_PRESSURE_OK";
NETWORK
TITLE ==80FAN93-S32F PRESSURE MONITORING

      U     #RelError;
      =     L     18.0;
      BLD   103;
      U     "80FAN93_PRESSURE_OK";
      =     L     18.1;
      BLD   103;
      U     "DB_GRP_80".FAN93.SM.MotorOn;
      =     L     18.2;
      BLD   103;
      U     #ErrorConfirm;
      =     L     18.3;
      BLD   103;
      CALL "FC_ANALOG_DIGIT_MOTOR" (
           REL_ERROR                := L     18.0,
           INPUT_ANALOG             := "R22-80FAN93+X-B32F-XS1:4",
           INPUT_BINARY             := L     18.1,
           I_MAX                    := 2.764800e+004,
           O_MIN                    := 0.000000e+000,
           O_MAX                    := 2.500000e+003,
           MOTOR_ON                 := L     18.2,
           MOTOR_DELAY              := 3.000000e+001,
           MAX_TIME                 := 30,
           ERROR_CONFIRM            := L     18.3,
           DDB                      := "DB_GRP_80".FAN93_PRESSURE);
      NOP   0;
NETWORK
TITLE =PRESSURE ERROR 80FAN93

      U     "DB_GRP_80".FAN93_PRESSURE.FM.Alarm;
      =     "PRESS_80FAN93_ERROR";
NETWORK
TITLE ==80FAN94-U1 CONTROL/ERROR RELEASE

      U     "LOG_1";
      =     L     18.0;
      U     L     18.0;
      U     #RelControlCL;
      U     #RelControlCR;
      UN    "DB_DIGIT".FM.G80_FAN94_S32F;
      UN    "DB_DIGIT".FM.G84_DOO07;
      UN    "DB_DIGIT".FM.G84_MT34_L2;
      =     #RelControl;
      U     L     18.0;
      U     #RelErrorCL;
      U     #RelErrorCR;
      =     #RelError;
NETWORK
TITLE ==80FAN94-U1 EXHAUST AIR FAN AUTO OFF DELAY

      U     "CR_STOP_FANS";
      L     S5T#5S;
      SE    "T_80FAN94_ON_DELAY";
      NOP   0;
      NOP   0;
      NOP   0;
      NOP   0;
NETWORK
TITLE ==80FAN94-U1 EXHAUST AIR FAN CONTROL SIGNALS

      U     "DB_CABINET_R22".SM.CtrlRelease_A;
      =     L     18.0;
      U     L     18.0;
      U     "CR_START_FANS";
      L     S5T#10S;
      SE    "T_80FAN94_OFF_DELAY";
      NOP   0;
      NOP   0;
      NOP   0;
      U     "T_80FAN94_OFF_DELAY";
      =     #AutoOn;
      U     L     18.0;
      U(    ;
      O     "T_80FAN94_ON_DELAY";
      O     "DB_GRP_84".FAN71.SM.GeneralError;
      O     "DB_DIGIT".FM.G84_FAN71;
      O     "T_CR_ASU_CF";
      )     ;
      =     #AutoOff;
NETWORK
TITLE ==80FAN94-U1 EXHAUST AIR FAN ENABLE COAST DOWN

      U     "LOG_1";
      =     "DB_GRP_80".FAN94.SM.CoastDownEnabled;
NETWORK
TITLE =RESET USING ESTOP ON THE CABINET

      U     "DB_CABINET_R22".FM.ESTOP;
      =     "DB_GRP_80".FAN94.CW.ESTOP_Res;
NETWORK
TITLE =SBIT 80FAN94 RUNNING

      U     "DB_GRP_80".FAN94.SM.MotorOn;
      =     "S_80FAN94_RUNNING";
NETWORK
TITLE ==80FAN94-U1 EXHAUST AIR FAN

      U     #RelControl;
      =     L     18.0;
      BLD   103;
      U     #RelError;
      =     L     18.1;
      BLD   103;
      U     #AutoOn;
      =     L     18.2;
      BLD   103;
      U     #AutoOff;
      =     L     18.3;
      BLD   103;
      U     "R22-80FAN94+22H4-Q1:14";
      =     L     18.4;
      BLD   103;
      U     "LOG_1";
      =     L     18.5;
      BLD   103;
      U     #ErrorConfirm;
      =     L     18.6;
      BLD   103;
      U     "R22-80FAN94+94TG1-S1:14";
      =     L     18.7;
      BLD   103;
      U     "R22-80FAN94+94TG1-S2:14";
      =     L     19.0;
      BLD   103;
      U     "R22-80FAN94+94TG1-S3:24";
      =     L     19.1;
      BLD   103;
      CALL "FC_MOTOR_FC" (
           REL_CONTROL              := L     18.0,
           REL_ERROR                := L     18.1,
           CL                       := #CL,
           CR                       := #CR,
           AUTO_START               := L     18.2,
           AUTO_STOP                := L     18.3,
           MPS                      := L     18.4,
           PTC_WAR                  := L     18.5,
           ERROR_CONFIRM            := L     18.6,
           FC_STATUS                := "R22-80FAN94-22H4-STAT",
           FC_DI                    := "R22-80FAN94-22H4-DI",
           FC_FREQ_AV               := "R22-80FAN94-22H4-FRQAV",
           MAX_TIME_RAMP            := 30,
           SW_ENABLE                := L     18.7,
           SW_START                 := L     19.0,
           SW_STOP                  := L     19.1,
           FC_CTRL                  := "R22-80FAN94-22H4-CTRL",
           FC_FREQ_SP               := "R22-80FAN94-22H4-FRQSP",
           LAMP_ON                  := "R22-80FAN94+94TG1-H2:x1",
           DELAY_ON                 := "DELAY_ON",
           DDB                      := "DB_GRP_80".FAN94);
      NOP   0;
NETWORK
TITLE ==80FAN94-S32F PRESSURE STATUS TRANSFER

      U     "FDB_DIGIT".R22_80FAN94_PRESS_OK;
      =     "80FAN94_PRESSURE_OK";
NETWORK
TITLE ==80FAN94-S32F PRESSURE MONITORING

      U     #RelError;
      =     L     18.0;
      BLD   103;
      U     "DB_GRP_80".FAN94.SM.MotorOn;
      =     L     18.1;
      BLD   103;
      U     "80FAN94_PRESSURE_OK";
      =     L     18.2;
      BLD   103;
      U(    ;
      O     "R22-0AB59+22H1-S6:14";
      O     "R16-0AB59+16H1-S6:14";
      O     "R17-0QB59+17H1-S6:14";
      O     "R25-0AB59+25H1-S6:14";
      )     ;
      =     L     18.3;
      BLD   103;
      CALL "FC_MOTOR_PRESSURE" (
           REL_ERROR                := L     18.0,
           MOTOR_ON                 := L     18.1,
           PRESSURE                 := L     18.2,
           TIME_ON                  := 30,
           TIME_OFF                 := 30,
           ERROR_CONFIRM            := L     18.3,
           FM_PRESSURE              := "PRESS_80FAN94_ERROR",
           SM_PRESSURE              := "DB_DIGIT".SM.G80_FAN94_S32F,
           TIMER_PRESSURE           := "DB_GRP_80".FAN94.PV.PressureTimer);
      NOP   0;
NETWORK
TITLE =PRESSURE ERROR 80FAN94

      U(    ;
      O     "R22-0AB59+22H1-S6:14";
      O     "R16-0AB59+16H1-S6:14";
      O     "R17-0QB59+17H1-S6:14";
      O     "R25-0AB59+25H1-S6:14";
      )     ;
      R     "DB_DIGIT".FM.G80_FAN94_S32F;
      U(    ;
      O     "PRESS_80FAN94_ERROR";
      O     "FDB_DIGIT".PRES_80FAN94_ERROR;
      )     ;
      U     #RelError;
      S     "DB_DIGIT".FM.G80_FAN94_S32F;
      NOP   0;
NETWORK
TITLE ==80FAN94-B85 VIBRATION MONITORING

      U     #RelError;
      =     L     18.0;
      BLD   103;
      U     "DB_GRP_80".FAN94.SM.MotorOn;
      =     L     18.1;
      BLD   103;
      UN    "R22-80FAN94+22H4-A85:25";
      =     L     18.2;
      BLD   103;
      UN    "R22-80FAN94+22H4-A85:27";
      =     L     18.3;
      BLD   103;
      U     #ErrorConfirm;
      =     L     18.4;
      BLD   103;
      CALL "FC_MOTOR_VIBRATION" (
           REL_ERROR                := L     18.0,
           MOTOR_ON                 := L     18.1,
           PRE_ALARM                := L     18.2,
           ALARM                    := L     18.3,
           ERROR_CONFIRM            := L     18.4,
           DDB                      := "DB_VIBRATION_SENSORS".V_80FAN94_A85);
      NOP   0;
NETWORK
TITLE ==80FAN95-U1 CONTROL/ERROR RELEASE

      U     "LOG_1";
      =     L     18.0;
      U     L     18.0;
      U     #RelControlCL;
      U     #RelControlCR;
      U(    ;
      O     "DB_GRP_80".FLA97.SM.Open;
      ON    "DB_GRP_80".FLA97.SM.Open;
      )     ;
      U(    ;
      O     "DB_GRP_80".FLA97_M2.SM.Open;
      ON    "DB_GRP_80".FLA97_M2.SM.Open;
      )     ;
      UN    "DB_GRP_80".FAN95_PRESSURE.FM.L01_MinErr;
      UN    "DB_GRP_80".FAN95_PRESSURE.FM.Alarm;
      U(    ;
      ON    "FDB_DIGIT".PRES_80FAN95_ERROR;
      O     "FDB_DIGIT".PRES_80FAN95_ERROR;
      )     ;
      UN    "DB_PROG".PRIMER.SM.CLEANING_MODE_IS_ON;
      =     #RelControl;
      U     L     18.0;
      U     #RelErrorCL;
      U     #RelErrorCR;
      =     #RelError;
NETWORK
TITLE ==80FAN95-U1 CONTROL SIGNALS

      U     "DB_CABINET_R22".SM.CtrlRelease_A;
      =     L     18.0;
      U     L     18.0;
      U     "PR_START_PROD_FANS";
      U(    ;
      O     "T_PR_FANS_DELAY_25_S";
      O     "PR_START_PROD_FANS";
      )     ;
      UN    "DB_GRP_80".FAN95.SM.GeneralError;
      =     #AutoOn;
      U     L     18.0;
      U(    ;
      U     "PR_STOP_PROD_FANS";
      UN    "DB_PROG".PRIMER.SM.ASU_ON;
      U     "T_ASU_STOPPED_DELAY";
      O     "DB_GRP_80".FAN95.SM.GeneralError;
      O     ;
      U     "DB_GRP_83".FAN91.SM.GeneralError;
      UN    "DB_GRP_83".FAN91.SM.GeneralError;
      O     "DB_GRP_83".FAN91_PRESSURE.FM.L01_MinErr;
      O     ;
      U     "T_83FAN91_CF";
      UN    "LOG_1";
      )     ;
      =     #AutoOff;
NETWORK
TITLE =80FAN95-U1 ENABLE COAST DOWN

      U     "LOG_1";
      =     "DB_GRP_80".FAN95.SM.CoastDownEnabled;
NETWORK
TITLE =RESET USING ESTOP ON THE CABINET

      U     "DB_CABINET_R22".FM.ESTOP;
      =     "DB_GRP_80".FAN95.CW.ESTOP_Res;
NETWORK
TITLE =SBIT 80FAN95 RUNNING

      U     "DB_GRP_80".FAN95.SM.MotorOn;
      =     "S_80FAN95_RUNNING";
NETWORK
TITLE ==80FAN95-U1 EXHAUST AIR FAN

      U     #RelControl;
      =     L     18.0;
      BLD   103;
      U     #RelError;
      =     L     18.1;
      BLD   103;
      U     #AutoOn;
      =     L     18.2;
      BLD   103;
      U     #AutoOff;
      =     L     18.3;
      BLD   103;
      U     "R22-80FAN95+22H4-Q1:14";
      =     L     18.4;
      BLD   103;
      U     "LOG_1";
      =     L     18.5;
      BLD   103;
      U     #ErrorConfirm;
      =     L     18.6;
      BLD   103;
      U     "R22-80FAN95+95TG1-S1:14";
      =     L     18.7;
      BLD   103;
      U     "R22-80FAN95+95TG1-S2:14";
      =     L     19.0;
      BLD   103;
      U     "R22-80FAN95+95TG1-S3:24";
      =     L     19.1;
      BLD   103;
      CALL "FC_MOTOR_FC" (
           REL_CONTROL              := L     18.0,
           REL_ERROR                := L     18.1,
           CL                       := #CL,
           CR                       := #CR,
           AUTO_START               := L     18.2,
           AUTO_STOP                := L     18.3,
           MPS                      := L     18.4,
           PTC_WAR                  := L     18.5,
           ERROR_CONFIRM            := L     18.6,
           FC_STATUS                := "R22-80FAN95-22H4-STAT",
           FC_DI                    := "R22-80FAN95-22H4-DI",
           FC_FREQ_AV               := "R22-80FAN95-22H4-FRQAV",
           MAX_TIME_RAMP            := 30,
           SW_ENABLE                := L     18.7,
           SW_START                 := L     19.0,
           SW_STOP                  := L     19.1,
           FC_CTRL                  := "R22-80FAN95-22H4-CTRL",
           FC_FREQ_SP               := "R22-80FAN95-22H4-FRQSP",
           LAMP_ON                  := "R22-80FAN95+95TG1-H2:x1",
           DELAY_ON                 := "DELAY_ON",
           DDB                      := "DB_GRP_80".FAN95);
      NOP   0;
NETWORK
TITLE ==80FAN95-S32F PRESSURE STATUS TRANSFER

      U     "FDB_DIGIT".R22_80FAN95_PRESS_OK;
      =     "80FAN95_PRESSURE_OK";
NETWORK
TITLE ==80FAN95-S32F PRESSURE MONITORING

      U     #RelError;
      =     L     18.0;
      BLD   103;
      U     "80FAN95_PRESSURE_OK";
      =     L     18.1;
      BLD   103;
      U     "DB_GRP_80".FAN95.SM.MotorOn;
      =     L     18.2;
      BLD   103;
      U     #ErrorConfirm;
      =     L     18.3;
      BLD   103;
      CALL "FC_ANALOG_DIGIT_MOTOR" (
           REL_ERROR                := L     18.0,
           INPUT_ANALOG             := "R22-80FAN95+X-B32F-XS1:4",
           INPUT_BINARY             := L     18.1,
           I_MAX                    := 2.764800e+004,
           O_MIN                    := 0.000000e+000,
           O_MAX                    := 2.500000e+003,
           MOTOR_ON                 := L     18.2,
           MOTOR_DELAY              := 4.000000e+001,
           MAX_TIME                 := 55,
           ERROR_CONFIRM            := L     18.3,
           DDB                      := "DB_GRP_80".FAN95_PRESSURE);
      NOP   0;
NETWORK
TITLE =PRESSURE ERROR 80FAN95

      U     "DB_GRP_80".FAN95_PRESSURE.FM.Alarm;
      =     "PRESS_80FAN95_ERROR";
NETWORK
TITLE ==80FAN95-B85 VIBRATION MONITORING

      U     #RelError;
      =     L     18.0;
      BLD   103;
      U     "DB_GRP_80".FAN95.SM.MotorOn;
      =     L     18.1;
      BLD   103;
      UN    "R22-80FAN94+22H4-A85:29";
      =     L     18.2;
      BLD   103;
      UN    "R22-80FAN94+22H4-A85:31";
      =     L     18.3;
      BLD   103;
      U     #ErrorConfirm;
      =     L     18.4;
      BLD   103;
      CALL "FC_MOTOR_VIBRATION" (
           REL_ERROR                := L     18.0,
           MOTOR_ON                 := L     18.1,
           PRE_ALARM                := L     18.2,
           ALARM                    := L     18.3,
           ERROR_CONFIRM            := L     18.4,
           DDB                      := "DB_VIBRATION_SENSORS".V_80FAN95_A85);
      NOP   0;
NETWORK
TITLE =

NETWORK
TITLE =
//NEW EXHAUST SCRUBBER - ZONE CC
NETWORK
TITLE ==80FAN96-U1 CONTROL/ERROR RELEASE

      U     "LOG_1";
      =     L     18.0;
      U     L     18.0;
      U     #RelControlCL;
      U     #RelControlCR;
      UN    "DB_PROG".PRIMER.SM.CLEANING_MODE_IS_ON;
      =     #RelControl;
      U     L     18.0;
      U     #RelErrorCL;
      U     #RelErrorCR;
      =     #RelError;
NETWORK
TITLE ==80FAN96-U1 CONTROL SIGNALS

      U     "DB_CABINET_R22".SM.CtrlRelease_A;
      =     L     18.0;
      U     L     18.0;
      U     "PR_START_PROD_FANS";
      U     "T_PR_FANS_DELAY_25_S";
      UN    "DB_GRP_80_SCRB".FAN96.SM.GeneralError;
      UN    "DB_DIGIT".FM.G80_FAN96_PSA101;
      =     #AutoOn;
      U     L     18.0;
      U(    ;
      U     "PR_STOP_PROD_FANS";
      UN    "DB_PROG".PRIMER.SM.ASU_ON;
      U     "T_ASU_STOPPED_DELAY";
      O     "DB_DIGIT".FM.G80_FAN96_PSA101;
      O     ;
      U     "T_83FAN91_CF";
      UN    "LOG_1";
      )     ;
      =     #AutoOff;
NETWORK
TITLE ==80FAN96-U1 GENERAL ERROR

      U     "LOG_1";
      =     L     18.0;
      U     L     18.0;
      U     "DB_GRP_80_SCRB".FAN96.SM.GeneralError;
      =     "SMarker_80FAN96_GenError";
      U     L     18.0;
      U     "DB_GRP_80_SCRB".FAN96.SM.MotorOn;
      =     "SBIT 80FAN96 RUNNING";
NETWORK
TITLE =MOVE FREQUENCY SETPOINT B0 EXHAUST =80FAN96-U1

      U     "LOG_1";
      =     L     18.0;
      U     L     18.0;
      U(    ;
      L     "DB_GRP_80_SCRB".FAN96.PV.Frq_SP;
      L     1.000000e+001;
      <R    ;
      )     ;
      SPBNB _011;
      L     1.000000e+001;
      T     "DB_GRP_80_SCRB".FAN96.PV.Frq_SP;
_011: NOP   0;
      U     L     18.0;
      U(    ;
      L     "DB_GRP_80_SCRB".FAN96.PV.Frq_SP;
      L     5.000000e+001;
      >R    ;
      )     ;
      SPBNB _012;
      L     5.000000e+001;
      T     "DB_GRP_80_SCRB".FAN96.PV.Frq_SP;
_012: NOP   0;
NETWORK
TITLE =COAST DOWN ENABLED 80FAN96

      U     "LOG_0";
      =     "DB_GRP_80_SCRB".FAN96.SM.CoastDownEnabled;
NETWORK
TITLE ==80FAN96-U1 HEAT-UP FAN

      U     #RelControl;
      =     L     18.0;
      BLD   103;
      U     #RelError;
      =     L     18.1;
      BLD   103;
      U     #AutoOn;
      =     L     18.2;
      BLD   103;
      U     #AutoOff;
      =     L     18.3;
      BLD   103;
      U     "E763.0";
      =     L     18.4;
      BLD   103;
      U     "E763.2";
      =     L     18.5;
      BLD   103;
      U     "E763.1";
      =     L     18.6;
      BLD   103;
      U     #ErrorConfirm;
      =     L     18.7;
      BLD   103;
      U     "E766.0";
      =     L     19.0;
      BLD   103;
      U     "E766.1";
      =     L     19.1;
      BLD   103;
      U     "E766.2";
      =     L     19.2;
      BLD   103;
      CALL "FC_VFD_GHISALBA" (
           REL_CONTROL              := L     18.0,
           REL_ERROR                := L     18.1,
           CL                       := #CL,
           CR                       := #CR,
           AUTO_START               := L     18.2,
           AUTO_STOP                := L     18.3,
           MPS_VFD                  := L     18.4,
           MLKS_VFD                 := L     18.5,
           PTC_Motor                := L     18.6,
           RST_ALLARM               := L     18.7,
           W_Rd_Faults              := EW  6430,
           W_Rd_Status              := EW  6432,
           W_Rd_VFD_Freq            := EW  6436,
           MAX_TIME_RAMP            := 60,
           SW_ENABLE                := L     19.0,
           SW_START                 := L     19.1,
           SW_STOP                  := L     19.2,
           FC_CTRL                  := AW  6430,
           FC_FREQ_SP               := AW  6432,
           FC_CTRL_1                := AW  6434,
           LAMP_ON                  := "A761.2",
           DELAY_ON                 := "DELAY_ON_30",
           DDB                      := "DB_GRP_80_SCRB".FAN96);
      NOP   0;
NETWORK
TITLE ==80FAN96-PSA101 CONTROL PRESSURE

      U     #RelError;
      =     L     18.0;
      BLD   103;
      U     "DB_GRP_80_SCRB".FAN96.SM.MotorOn;
      =     L     18.1;
      BLD   103;
      U     "E763.3";
      =     L     18.2;
      BLD   103;
      U     #ErrorConfirm;
      =     L     18.3;
      BLD   103;
      CALL "FC_MOTOR_PRESSURE" (
           REL_ERROR                := L     18.0,
           MOTOR_ON                 := L     18.1,
           PRESSURE                 := L     18.2,
           TIME_ON                  := 60,
           TIME_OFF                 := 60,
           ERROR_CONFIRM            := L     18.3,
           FM_PRESSURE              := "DB_DIGIT".FM.G80_FAN96_PSA101,
           SM_PRESSURE              := "DB_DIGIT".SM.G80_FAN96_PSA101,
           TIMER_PRESSURE           := "DB_GRP_80_SCRB".FAN96.PV.Runtime);
      NOP   0;
NETWORK
TITLE =VIBRATION SENSOR =80FAN96

      U     #RelError;
      =     L     18.0;
      BLD   103;
      U     "DB_GRP_80_SCRB".FAN96.SM.MotorOn;
      =     L     18.1;
      BLD   103;
      UN    "E772.4";
      =     L     18.2;
      BLD   103;
      UN    "E772.5";
      =     L     18.3;
      BLD   103;
      U     #ErrorConfirm;
      =     L     18.4;
      BLD   103;
      CALL "FC_MOTOR_VIBRATION" (
           REL_ERROR                := L     18.0,
           MOTOR_ON                 := L     18.1,
           PRE_ALARM                := L     18.2,
           ALARM                    := L     18.3,
           ERROR_CONFIRM            := L     18.4,
           DDB                      := "DB_GRP_80_SCRB".FAN96_VIBR);
      NOP   0;
NETWORK
TITLE =****** RUNTIME METER ********

NETWORK
TITLE =MOVE SETPOINT VALUE FOR RUNTIME OF =80FAN96

      L     1.000000e+003;
      T     "DB_GRP_80_SCRB".FAN96_TIME.SETPOINT;
      NOP   0;
NETWORK
TITLE =RUNTIME OF =80FAN96

      U     "DB_GRP_80_SCRB".FAN96.SM.MotorOn;
      =     L     18.0;
      BLD   103;
      U(    ;
      O     "DB_GRP_80_SCRB".FAN96_TIME.RESET_PLC;
      O     "DB_GRP_80_SCRB".FAN96_TIME.RESET_HMI;
      )     ;
      =     L     18.1;
      BLD   103;
      CALL "FC_TIMER_SEC" (
           RUN                      := L     18.0,
           RESET                    := L     18.1,
           SP                       := "DB_GRP_80_SCRB".FAN96_TIME.SETPOINT,
           FACTOR                   := 3.600000e+003,
           H_REMAIN                 := "DB_GRP_80_SCRB".FAN96_TIME.H_REMAIN,
           M_REMAIN                 := "DB_GRP_80_SCRB".FAN96_TIME.M_REMAIN,
           S_REMAIN                 := "DB_GRP_80_SCRB".FAN96_TIME.S_REMAIN,
           TIME_ELAPSED             := "DB_GRP_80_SCRB".FAN96_TIME.TIME_ELAPSED,
           SECONDS                  := "DB_GRP_80_SCRB".FAN96_TIME.TIME_COUNTER_S);
      NOP   0;
NETWORK
TITLE =CONVERT ELAPSED TIME =80FAN96

      U(    ;
      U(    ;
      L     "DB_GRP_80_SCRB".FAN96_TIME.H_REMAIN;
      ITD   ;
      T     #Runtime_DI;
      SET   ;
      SAVE  ;
      CLR   ;
      U     BIE;
      )     ;
      SPBNB _013;
      L     #Runtime_DI;
      DTR   ;
      T     #Runtime_R;
      SET   ;
      SAVE  ;
      CLR   ;
_013: U     BIE;
      )     ;
      SPBNB _014;
      L     "DB_GRP_80_SCRB".FAN96_TIME.SETPOINT;
      L     #Runtime_R;
      -R    ;
      T     "DB_GRP_80_SCRB".FAN96_TIME.TIME_ELAPSED_H;
_014: NOP   0;
NETWORK
TITLE =

NETWORK
TITLE ==80FAN96 - 80FTR1101-PDI101 FILTER PRESSURE MONITORING

      U     #RelError;
      =     L     18.0;
      BLD   103;
      U     "LOG_1";
      =     L     18.1;
      BLD   103;
      U     "DB_GRP_80_SCRB".FAN96.SM.MotorOn;
      =     L     18.2;
      BLD   103;
      U     #ErrorConfirm;
      =     L     18.3;
      BLD   103;
      CALL "FC_ANALOG_DIGIT_MOTOR" (
           REL_ERROR                := L     18.0,
           INPUT_ANALOG             := "EW2312",
           INPUT_BINARY             := L     18.1,
           I_MAX                    := 2.764800e+004,
           O_MIN                    := 0.000000e+000,
           O_MAX                    := 6.000000e+002,
           MOTOR_ON                 := L     18.2,
           MOTOR_DELAY              := 3.000000e+001,
           MAX_TIME                 := 30,
           ERROR_CONFIRM            := L     18.3,
           DDB                      := "DB_GRP_80_SCRB".FTR1101_PDI101);
      NOP   0;
NETWORK
TITLE ==80FAN96 - 80FTR1101-PDI102 FILTER PRESSURE MONITORING

      U     #RelError;
      =     L     18.0;
      BLD   103;
      U     "LOG_1";
      =     L     18.1;
      BLD   103;
      U     "DB_GRP_80_SCRB".FAN96.SM.MotorOn;
      =     L     18.2;
      BLD   103;
      U     #ErrorConfirm;
      =     L     18.3;
      BLD   103;
      CALL "FC_ANALOG_DIGIT_MOTOR" (
           REL_ERROR                := L     18.0,
           INPUT_ANALOG             := "EW2314",
           INPUT_BINARY             := L     18.1,
           I_MAX                    := 2.764800e+004,
           O_MIN                    := 0.000000e+000,
           O_MAX                    := 6.000000e+002,
           MOTOR_ON                 := L     18.2,
           MOTOR_DELAY              := 3.000000e+001,
           MAX_TIME                 := 30,
           ERROR_CONFIRM            := L     18.3,
           DDB                      := "DB_GRP_80_SCRB".FTR1101_PDI102);
      NOP   0;
NETWORK
TITLE ==80FAN96 - SB10-PDI101 -  FILTER PRESSURE MONITORING

      U     #RelError;
      =     L     18.0;
      BLD   103;
      U     "LOG_1";
      =     L     18.1;
      BLD   103;
      U     "DB_GRP_80_SCRB".FAN96.SM.MotorOn;
      =     L     18.2;
      BLD   103;
      U     #ErrorConfirm;
      =     L     18.3;
      BLD   103;
      CALL "FC_ANALOG_DIGIT_MOTOR" (
           REL_ERROR                := L     18.0,
           INPUT_ANALOG             := "EW2316",
           INPUT_BINARY             := L     18.1,
           I_MAX                    := 2.764800e+004,
           O_MIN                    := 0.000000e+000,
           O_MAX                    := 6.000000e+002,
           MOTOR_ON                 := L     18.2,
           MOTOR_DELAY              := 3.000000e+001,
           MAX_TIME                 := 30,
           ERROR_CONFIRM            := L     18.3,
           DDB                      := "DB_GRP_80_SCRB".SB10_PDI101);
      NOP   0;
NETWORK
TITLE =

NETWORK
TITLE ==TSA101 80FAN96 MOTOR THERMAL PROBE OK (R22)

      UN    "DB_GRP_80_SCRB".FAN96.FM.FCWarning;
      =     "DB_DIGIT".SM.G80_FAN96_TSA101;
      U     "DB_GRP_80_SCRB".FAN96.FM.FCWarning;
      =     "DB_DIGIT".FM.G80_FAN96_TSA101;

NETWORK
TITLE =END

END_FUNCTION

